# TR-1um cell library — generated by scripts/mklef.py
# source: TR-1um_STDCELL.gds

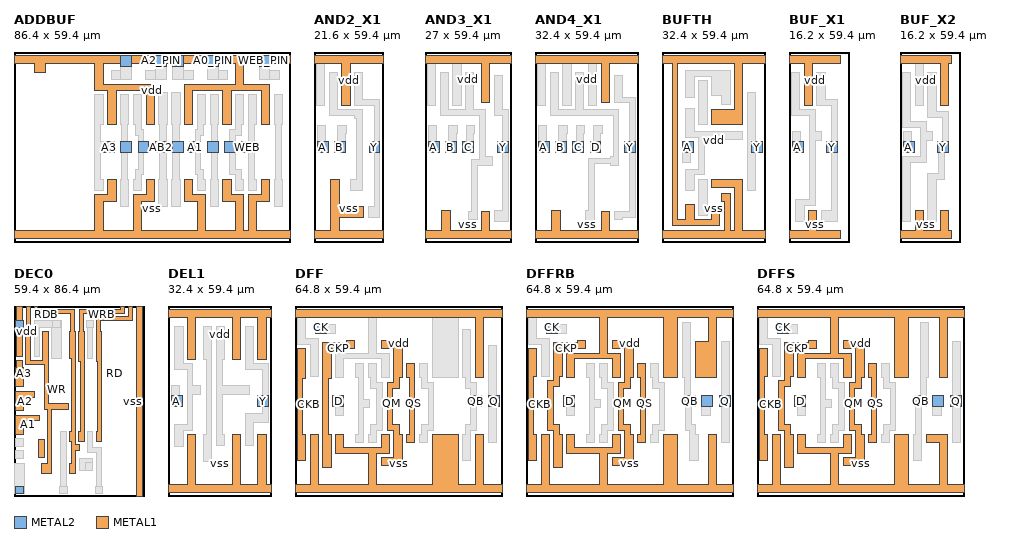
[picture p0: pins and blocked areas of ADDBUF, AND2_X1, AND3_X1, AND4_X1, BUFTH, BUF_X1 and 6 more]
MACRO ADDBUF
  CLASS BLOCK ;
  FOREIGN ADDBUF 48.600 -0.000 ;
  ORIGIN 0.000 0.000 ;
  SIZE 86.400 BY 59.400 ;
  SYMMETRY X Y ;
  PIN A0
    DIRECTION INOUT ;
    USE SIGNAL ;
    PORT
      LAYER METAL2 ;
        RECT 65.800 28.000 69.200 31.400 ;
    END
  END A0
  PIN A0_PIN
    DIRECTION INOUT ;
    USE SIGNAL ;
    PORT
      LAYER METAL2 ;
        RECT 60.400 54.900 63.800 58.300 ;
    END
  END A0_PIN
  PIN A1
    DIRECTION INOUT ;
    USE SIGNAL ;
    PORT
      LAYER METAL2 ;
        RECT 55.000 28.000 58.400 31.400 ;
    END
  END A1
  PIN A1_PIN
    DIRECTION INOUT ;
    USE SIGNAL ;
    PORT
      LAYER METAL2 ;
        RECT 49.600 54.900 53.000 58.300 ;
    END
  END A1_PIN
  PIN A2
    DIRECTION INOUT ;
    USE SIGNAL ;
    PORT
      LAYER METAL2 ;
        RECT 38.800 28.000 42.200 31.400 ;
    END
  END A2
  PIN A2_PIN
    DIRECTION INOUT ;
    USE SIGNAL ;
    PORT
      LAYER METAL2 ;
        RECT 44.200 54.900 47.600 58.300 ;
    END
  END A2_PIN
  PIN A3
    DIRECTION INOUT ;
    USE SIGNAL ;
    PORT
      LAYER METAL2 ;
        RECT 28.000 28.000 31.400 31.400 ;
    END
  END A3
  PIN A3_PIN
    DIRECTION INOUT ;
    USE SIGNAL ;
    PORT
      LAYER METAL2 ;
        RECT 33.400 54.900 36.800 58.300 ;
    END
  END A3_PIN
  PIN AB0
    DIRECTION INOUT ;
    USE SIGNAL ;
    PORT
      LAYER METAL2 ;
        RECT 60.400 28.000 63.800 31.400 ;
    END
  END AB0
  PIN AB1
    DIRECTION INOUT ;
    USE SIGNAL ;
    PORT
      LAYER METAL2 ;
        RECT 49.600 28.000 53.000 31.400 ;
    END
  END AB1
  PIN AB2
    DIRECTION INOUT ;
    USE SIGNAL ;
    PORT
      LAYER METAL2 ;
        RECT 44.200 28.000 47.600 31.400 ;
    END
  END AB2
  PIN AB3
    DIRECTION INOUT ;
    USE SIGNAL ;
    PORT
      LAYER METAL2 ;
        RECT 33.400 28.000 36.800 31.400 ;
    END
  END AB3
  PIN WEB
    DIRECTION INOUT ;
    USE SIGNAL ;
    PORT
      LAYER METAL2 ;
        RECT 71.200 28.000 74.600 31.400 ;
    END
  END WEB
  PIN WEB_PIN
    DIRECTION INOUT ;
    USE SIGNAL ;
    PORT
      LAYER METAL2 ;
        RECT 76.600 54.900 80.000 58.300 ;
    END
  END WEB_PIN
  PIN vdd
    DIRECTION INOUT ;
    USE POWER ;
    SHAPE ABUTMENT ;
    PORT
      LAYER METAL1 ;
        POLYGON 29.300 47.400 29.300 36.600 31.900 36.600 31.900 47.400 41.300 47.400 41.300 36.600 43.900 36.600 43.900 49.200 27.900 49.200 27.900 55.700 69.300 55.700 69.300 49.200 53.300 49.200 53.300 36.600 55.900 36.600 55.900 47.400 65.300 47.400 65.300 36.600 67.900 36.600 67.900 47.400 77.300 47.400 77.300 36.600 79.900 36.600 79.900 49.200 71.900 49.200 71.900 55.700 86.400 55.700 86.400 58.300 0.000 58.300 0.000 55.700 6.400 55.700 6.400 53.100 9.800 53.100 9.800 55.700 25.300 55.700 25.300 47.400 ;
    END
  END vdd
  PIN vss
    DIRECTION INOUT ;
    USE GROUND ;
    SHAPE ABUTMENT ;
    PORT
      LAYER METAL1 ;
        POLYGON 39.900 12.800 43.900 12.800 43.900 19.600 41.300 19.600 41.300 14.800 37.300 14.800 37.300 3.700 27.900 3.700 27.900 12.800 31.900 12.800 31.900 19.600 29.300 19.600 29.300 14.800 25.300 14.800 25.300 3.700 0.000 3.700 0.000 1.100 86.400 1.100 86.400 3.700 75.900 3.700 75.900 12.800 79.900 12.800 79.900 19.600 77.300 19.600 77.300 14.800 73.300 14.800 73.300 3.700 71.900 3.700 71.900 14.800 67.900 14.800 67.900 19.600 65.300 19.600 65.300 12.800 69.300 12.800 69.300 3.700 59.900 3.700 59.900 14.800 55.900 14.800 55.900 19.600 53.300 19.600 53.300 12.800 57.300 12.800 57.300 3.700 39.900 3.700 ;
    END
  END vss
  OBS
    LAYER METAL1 ;
      POLYGON 83.000 53.500 80.000 53.500 80.000 54.300 76.600 54.300 76.600 50.900 83.000 50.900 ;
      POLYGON 36.800 54.300 33.400 54.300 33.400 53.500 30.400 53.500 30.400 50.900 36.800 50.900 ;
      POLYGON 47.600 54.300 44.200 54.300 44.200 53.500 41.200 53.500 41.200 50.900 47.600 50.900 ;
      POLYGON 56.000 53.500 53.000 53.500 53.000 54.300 49.600 54.300 49.600 50.900 56.000 50.900 ;
      POLYGON 66.800 53.500 63.800 53.500 63.800 54.300 60.400 54.300 60.400 50.900 66.800 50.900 ;
      POLYGON 51.600 36.600 51.900 36.600 51.900 46.800 49.300 46.800 49.300 36.600 49.600 36.600 49.600 31.400 51.600 31.400 ;
      POLYGON 47.600 36.600 47.900 36.600 47.900 46.800 45.300 46.800 45.300 36.600 45.600 36.600 45.600 31.400 47.600 31.400 ;
      POLYGON 40.600 35.200 39.900 35.200 39.900 46.000 37.300 46.000 37.300 36.600 38.100 36.600 38.100 33.400 38.800 33.400 38.800 31.400 40.600 31.400 ;
      POLYGON 83.900 19.600 83.600 19.600 83.600 36.600 83.900 36.600 83.900 46.000 81.300 46.000 81.300 36.600 81.600 36.600 81.600 19.600 81.300 19.600 81.300 11.200 83.900 11.200 ;
      POLYGON 27.100 36.600 27.900 36.600 27.900 46.000 25.300 46.000 25.300 16.200 27.900 16.200 27.900 19.600 27.100 19.600 27.100 28.000 28.000 28.000 28.000 31.400 27.100 31.400 ;
      POLYGON 35.600 36.600 35.900 36.600 35.900 46.000 33.300 46.000 33.300 36.600 33.600 36.600 33.600 31.400 35.600 31.400 ;
      POLYGON 58.400 33.400 59.100 33.400 59.100 36.600 59.900 36.600 59.900 46.000 57.300 46.000 57.300 35.200 56.600 35.200 56.600 31.400 58.400 31.400 ;
      POLYGON 63.600 36.600 63.900 36.600 63.900 46.000 61.300 46.000 61.300 36.600 61.600 36.600 61.600 31.400 63.600 31.400 ;
      POLYGON 69.200 33.400 71.100 33.400 71.100 36.600 71.900 36.600 71.900 46.000 69.300 46.000 69.300 35.200 67.400 35.200 67.400 31.400 69.200 31.400 ;
      POLYGON 74.600 28.000 73.300 28.000 73.300 16.200 75.900 16.200 75.900 19.600 75.100 19.600 75.100 36.600 75.900 36.600 75.900 46.000 73.300 46.000 73.300 31.400 74.600 31.400 ;
      POLYGON 45.300 19.600 45.300 11.200 47.900 11.200 47.900 19.600 47.600 19.600 47.600 28.000 45.600 28.000 45.600 19.600 ;
      POLYGON 33.300 19.600 33.300 11.200 35.900 11.200 35.900 19.600 35.600 19.600 35.600 28.000 33.600 28.000 33.600 19.600 ;
      POLYGON 69.300 21.000 69.300 16.200 71.900 16.200 71.900 19.600 71.100 19.600 71.100 22.800 69.200 22.800 69.200 28.000 67.400 28.000 67.400 21.000 ;
      POLYGON 61.300 19.600 61.300 11.200 63.900 11.200 63.900 19.600 63.600 19.600 63.600 28.000 61.600 28.000 61.600 19.600 ;
      POLYGON 38.100 22.800 38.100 19.600 37.300 19.600 37.300 16.200 39.900 16.200 39.900 21.000 40.600 21.000 40.600 28.000 38.800 28.000 38.800 22.800 ;
      POLYGON 57.300 21.000 57.300 16.200 59.900 16.200 59.900 19.600 59.100 19.600 59.100 22.800 58.400 22.800 58.400 28.000 56.600 28.000 56.600 21.000 ;
      POLYGON 49.300 19.600 49.300 11.200 51.900 11.200 51.900 19.600 51.600 19.600 51.600 28.000 49.600 28.000 49.600 19.600 ;
    LAYER METAL2 ;
      RECT 33.400 50.900 36.800 54.900 ;
      RECT 49.600 50.900 53.000 54.900 ;
      RECT 60.400 50.900 63.800 54.900 ;
      RECT 76.600 50.900 80.000 54.900 ;
      RECT 44.200 50.900 47.600 54.900 ;
  END
END ADDBUF

MACRO AND2_X1
  CLASS CORE ;
  FOREIGN AND2_X1 -0.000 -0.000 ;
  ORIGIN 0.000 0.000 ;
  SIZE 21.600 BY 59.400 ;
  SITE TR1UM ;
  SYMMETRY X Y ;
  PIN A
    DIRECTION INOUT ;
    USE SIGNAL ;
    PORT
      LAYER METAL2 ;
        RECT 1.000 28.000 4.400 31.400 ;
    END
  END A
  PIN B
    DIRECTION INOUT ;
    USE SIGNAL ;
    PORT
      LAYER METAL2 ;
        RECT 6.400 28.000 9.800 31.400 ;
    END
  END B
  PIN Y
    DIRECTION INOUT ;
    USE SIGNAL ;
    PORT
      LAYER METAL2 ;
        RECT 17.200 28.000 20.600 31.400 ;
    END
  END Y
  PIN vdd
    DIRECTION INOUT ;
    USE POWER ;
    SHAPE ABUTMENT ;
    PORT
      LAYER METAL1 ;
        POLYGON 11.300 42.700 11.300 55.700 21.600 55.700 21.600 58.300 0.000 58.300 0.000 55.700 8.700 55.700 8.700 42.700 ;
    END
  END vdd
  PIN vss
    DIRECTION INOUT ;
    USE GROUND ;
    SHAPE ABUTMENT ;
    PORT
      LAYER METAL1 ;
        POLYGON 0.000 1.100 21.600 1.100 21.600 3.700 7.900 3.700 7.900 7.700 15.500 7.700 15.500 11.100 7.900 11.100 7.900 19.600 5.300 19.600 5.300 3.700 0.000 3.700 ;
    END
  END vss
  OBS
    LAYER METAL1 ;
      RECT 0.700 42.700 3.300 55.700 ;
      POLYGON 20.600 44.600 15.300 44.600 15.300 52.900 12.700 52.900 12.700 42.700 18.800 42.700 18.800 31.400 20.600 31.400 ;
      POLYGON 15.200 41.300 7.300 41.300 7.300 52.900 4.700 52.900 4.700 39.500 12.600 39.500 12.600 38.700 13.400 38.700 13.400 19.600 11.500 19.600 11.500 16.200 15.200 16.200 ;
      POLYGON 9.800 33.900 10.100 33.900 10.100 36.500 7.500 36.500 7.500 31.400 9.800 31.400 ;
      RECT 1.000 31.400 3.600 36.500 ;
      POLYGON 16.900 11.100 16.900 7.700 20.600 7.700 20.600 28.000 18.800 28.000 18.800 11.100 ;
  END
END AND2_X1

MACRO AND3_X1
  CLASS CORE ;
  FOREIGN AND3_X1 -0.000 -0.000 ;
  ORIGIN 0.000 0.000 ;
  SIZE 27.000 BY 59.400 ;
  SITE TR1UM ;
  SYMMETRY X Y ;
  PIN A
    DIRECTION INOUT ;
    USE SIGNAL ;
    PORT
      LAYER METAL2 ;
        RECT 1.000 28.000 4.400 31.400 ;
    END
  END A
  PIN B
    DIRECTION INOUT ;
    USE SIGNAL ;
    PORT
      LAYER METAL2 ;
        RECT 6.400 28.000 9.800 31.400 ;
    END
  END B
  PIN C
    DIRECTION INOUT ;
    USE SIGNAL ;
    PORT
      LAYER METAL2 ;
        RECT 11.800 28.000 15.200 31.400 ;
    END
  END C
  PIN Y
    DIRECTION INOUT ;
    USE SIGNAL ;
    PORT
      LAYER METAL2 ;
        RECT 22.600 28.000 26.000 31.400 ;
    END
  END Y
  PIN vdd
    DIRECTION INOUT ;
    USE POWER ;
    SHAPE ABUTMENT ;
    PORT
      LAYER METAL1 ;
        POLYGON 20.300 43.500 20.300 55.700 27.000 55.700 27.000 58.300 0.000 58.300 0.000 55.700 17.700 55.700 17.700 43.500 ;
    END
  END vdd
  PIN vss
    DIRECTION INOUT ;
    USE GROUND ;
    SHAPE ABUTMENT ;
    PORT
      LAYER METAL1 ;
        POLYGON 0.000 1.100 27.000 1.100 27.000 3.700 20.300 3.700 20.300 9.500 17.700 9.500 17.700 3.700 7.900 3.700 7.900 9.900 5.300 9.900 5.300 3.700 0.000 3.700 ;
    END
  END vss
  OBS
    LAYER METAL1 ;
      RECT 8.700 42.700 11.300 55.700 ;
      RECT 0.700 42.700 3.300 55.700 ;
      POLYGON 16.300 24.000 21.200 24.000 21.200 26.600 18.900 26.600 18.900 41.300 15.300 41.300 15.300 52.900 12.700 52.900 12.700 41.300 7.300 41.300 7.300 52.900 4.700 52.900 4.700 39.500 17.100 39.500 17.100 25.800 14.500 25.800 14.500 9.500 13.700 9.500 13.700 6.900 16.300 6.900 ;
      POLYGON 26.000 41.300 24.300 41.300 24.300 52.100 21.700 52.100 21.700 39.500 24.200 39.500 24.200 31.400 26.000 31.400 ;
      RECT 1.000 31.400 3.600 36.500 ;
      POLYGON 9.800 33.900 10.100 33.900 10.100 36.500 7.500 36.500 7.500 31.400 9.800 31.400 ;
      POLYGON 15.200 33.900 15.500 33.900 15.500 36.500 12.900 36.500 12.900 31.400 15.200 31.400 ;
      POLYGON 21.700 9.900 21.700 6.500 26.000 6.500 26.000 28.000 24.200 28.000 24.200 9.900 ;
  END
END AND3_X1

MACRO AND4_X1
  CLASS CORE ;
  FOREIGN AND4_X1 -0.000 -0.000 ;
  ORIGIN 0.000 0.000 ;
  SIZE 32.400 BY 59.400 ;
  SITE TR1UM ;
  SYMMETRY X Y ;
  PIN A
    DIRECTION INOUT ;
    USE SIGNAL ;
    PORT
      LAYER METAL2 ;
        RECT 1.000 28.000 4.400 31.400 ;
    END
  END A
  PIN B
    DIRECTION INOUT ;
    USE SIGNAL ;
    PORT
      LAYER METAL2 ;
        RECT 6.400 28.000 9.800 31.400 ;
    END
  END B
  PIN C
    DIRECTION INOUT ;
    USE SIGNAL ;
    PORT
      LAYER METAL2 ;
        RECT 11.800 28.000 15.200 31.400 ;
    END
  END C
  PIN D
    DIRECTION INOUT ;
    USE SIGNAL ;
    PORT
      LAYER METAL2 ;
        RECT 17.200 28.000 20.600 31.400 ;
    END
  END D
  PIN Y
    DIRECTION INOUT ;
    USE SIGNAL ;
    PORT
      LAYER METAL2 ;
        RECT 28.000 28.000 31.400 31.400 ;
    END
  END Y
  PIN vdd
    DIRECTION INOUT ;
    USE POWER ;
    SHAPE ABUTMENT ;
    PORT
      LAYER METAL1 ;
        POLYGON 23.400 43.500 23.400 55.700 32.400 55.700 32.400 58.300 0.000 58.300 0.000 55.700 20.800 55.700 20.800 43.500 ;
    END
  END vdd
  PIN vss
    DIRECTION INOUT ;
    USE GROUND ;
    SHAPE ABUTMENT ;
    PORT
      LAYER METAL1 ;
        POLYGON 0.000 1.100 32.400 1.100 32.400 3.700 23.400 3.700 23.400 9.500 20.800 9.500 20.800 3.700 7.900 3.700 7.900 9.900 5.300 9.900 5.300 3.700 0.000 3.700 ;
    END
  END vss
  OBS
    LAYER METAL1 ;
      RECT 16.700 42.700 19.300 55.700 ;
      RECT 0.700 42.700 3.300 55.700 ;
      RECT 8.700 42.700 11.300 55.700 ;
      POLYGON 15.900 6.500 18.500 6.500 18.500 24.400 23.600 24.400 23.600 24.000 26.200 24.000 26.200 41.300 15.300 41.300 15.300 52.900 12.700 52.900 12.700 41.300 7.300 41.300 7.300 52.900 4.700 52.900 4.700 39.500 24.400 39.500 24.400 26.600 23.600 26.600 23.600 26.200 16.700 26.200 16.700 9.900 15.900 9.900 ;
      POLYGON 31.400 45.300 27.400 45.300 27.400 52.100 24.800 52.100 24.800 43.500 29.600 43.500 29.600 31.400 31.400 31.400 ;
      POLYGON 20.600 33.900 21.000 33.900 21.000 36.500 18.300 36.500 18.300 31.400 20.600 31.400 ;
      POLYGON 15.200 33.900 15.500 33.900 15.500 36.500 12.900 36.500 12.900 31.400 15.200 31.400 ;
      RECT 1.000 31.400 3.600 36.500 ;
      POLYGON 9.800 33.900 10.100 33.900 10.100 36.500 7.500 36.500 7.500 31.400 9.800 31.400 ;
      POLYGON 24.800 6.900 27.400 6.900 27.400 7.700 31.400 7.700 31.400 28.000 29.600 28.000 29.600 9.500 24.800 9.500 ;
  END
END AND4_X1

MACRO BUFTH
  CLASS CORE ;
  FOREIGN BUFTH -0.000 -0.000 ;
  ORIGIN 0.000 0.000 ;
  SIZE 32.400 BY 59.400 ;
  SITE TR1UM ;
  SYMMETRY X Y ;
  PIN A
    DIRECTION INOUT ;
    USE SIGNAL ;
    PORT
      LAYER METAL2 ;
        RECT 6.400 28.000 9.800 31.400 ;
    END
  END A
  PIN Y
    DIRECTION INOUT ;
    USE SIGNAL ;
    PORT
      LAYER METAL2 ;
        RECT 28.000 28.000 31.400 31.400 ;
    END
  END Y
  PIN vdd
    DIRECTION INOUT ;
    USE POWER ;
    SHAPE ABUTMENT ;
    PORT
      LAYER METAL1 ;
        POLYGON 18.100 5.100 18.100 10.900 15.500 10.900 15.500 6.900 10.100 6.900 10.100 11.700 7.500 11.700 7.500 6.900 5.000 6.900 5.000 55.700 22.700 55.700 22.700 41.300 15.500 41.300 15.500 36.600 25.300 36.600 25.300 55.700 32.400 55.700 32.400 58.300 0.000 58.300 0.000 55.700 3.200 55.700 3.200 5.100 ;
    END
  END vdd
  PIN vss
    DIRECTION INOUT ;
    USE GROUND ;
    SHAPE ABUTMENT ;
    PORT
      LAYER METAL1 ;
        POLYGON 0.000 1.100 32.400 1.100 32.400 3.700 25.300 3.700 25.300 19.600 15.500 19.600 15.500 17.000 22.700 17.000 22.700 3.700 21.300 3.700 21.300 15.300 18.700 15.300 18.700 12.700 19.500 12.700 19.500 3.700 0.000 3.700 ;
    END
  END vss
  OBS
    LAYER METAL1 ;
      POLYGON 21.300 53.600 7.500 53.600 7.500 45.300 10.100 45.300 10.100 51.800 15.500 51.800 15.500 45.700 18.700 45.700 18.700 43.100 21.300 43.100 ;
      RECT 11.500 36.600 14.100 50.400 ;
      POLYGON 29.300 46.800 26.700 46.800 26.700 16.200 29.300 16.200 29.300 28.000 28.000 28.000 28.000 31.400 29.300 31.400 ;
      POLYGON 10.100 21.000 13.200 21.000 13.200 32.000 25.300 32.000 25.300 34.600 10.100 34.600 10.100 41.700 7.500 41.700 7.500 32.800 11.400 32.800 11.400 22.800 7.500 22.800 7.500 16.200 10.100 16.200 ;
      RECT 6.400 25.000 9.000 28.000 ;
      RECT 11.500 8.300 14.100 19.600 ;
  END
END BUFTH

MACRO BUF_X1
  CLASS CORE ;
  FOREIGN BUF_X1 -0.000 -0.000 ;
  ORIGIN 0.000 0.000 ;
  SIZE 16.200 BY 59.400 ;
  SITE TR1UM ;
  SYMMETRY X Y ;
  PIN A
    DIRECTION INOUT ;
    USE SIGNAL ;
    PORT
      LAYER METAL2 ;
        RECT 1.000 28.000 4.400 31.400 ;
    END
  END A
  PIN Y
    DIRECTION INOUT ;
    USE SIGNAL ;
    PORT
      LAYER METAL2 ;
        RECT 11.800 28.000 15.200 31.400 ;
    END
  END Y
  PIN vdd
    DIRECTION INOUT ;
    USE POWER ;
    SHAPE ABUTMENT ;
    PORT
      LAYER METAL1 ;
        POLYGON 7.300 42.700 7.300 55.700 16.200 55.700 16.200 58.300 0.000 58.300 0.000 55.700 4.700 55.700 4.700 42.700 ;
    END
  END vdd
  PIN vss
    DIRECTION INOUT ;
    USE GROUND ;
    SHAPE ABUTMENT ;
    PORT
      LAYER METAL1 ;
        POLYGON 0.000 1.100 16.200 1.100 16.200 3.700 8.700 3.700 8.700 9.900 6.100 9.900 6.100 3.700 0.000 3.700 ;
    END
  END vss
  OBS
    LAYER METAL1 ;
      POLYGON 15.200 44.500 11.300 44.500 11.300 52.900 8.700 52.900 8.700 42.700 13.400 42.700 13.400 31.400 15.200 31.400 ;
      POLYGON 4.700 11.500 8.300 11.500 8.300 31.800 10.100 31.800 10.100 34.400 8.300 34.400 8.300 41.300 3.300 41.300 3.300 52.900 0.700 52.900 0.700 39.500 6.500 39.500 6.500 13.300 2.100 13.300 2.100 6.500 4.700 6.500 ;
      RECT 1.000 31.400 3.600 34.400 ;
      POLYGON 10.100 9.900 10.100 6.500 15.200 6.500 15.200 28.000 13.400 28.000 13.400 9.900 ;
  END
END BUF_X1

MACRO BUF_X2
  CLASS CORE ;
  FOREIGN BUF_X2 -0.000 -0.000 ;
  ORIGIN 0.000 0.000 ;
  SIZE 16.200 BY 59.400 ;
  SITE TR1UM ;
  SYMMETRY X Y ;
  PIN A
    DIRECTION INOUT ;
    USE SIGNAL ;
    PORT
      LAYER METAL2 ;
        RECT 1.000 28.000 4.400 31.400 ;
    END
  END A
  PIN Y
    DIRECTION INOUT ;
    USE SIGNAL ;
    PORT
      LAYER METAL2 ;
        RECT 11.800 28.000 15.200 31.400 ;
    END
  END Y
  PIN vdd
    DIRECTION INOUT ;
    USE POWER ;
    SHAPE ABUTMENT ;
    PORT
      LAYER METAL1 ;
        POLYGON 15.300 42.700 15.300 55.700 16.200 55.700 16.200 58.300 0.000 58.300 0.000 55.700 12.700 55.700 12.700 42.700 ;
    END
  END vdd
  PIN vss
    DIRECTION INOUT ;
    USE GROUND ;
    SHAPE ABUTMENT ;
    PORT
      LAYER METAL1 ;
        POLYGON 0.000 1.100 16.200 1.100 16.200 3.700 15.300 3.700 15.300 9.900 12.700 9.900 12.700 3.700 7.300 3.700 7.300 9.900 4.700 9.900 4.700 3.700 0.000 3.700 ;
    END
  END vss
  OBS
    LAYER METAL1 ;
      RECT 4.700 42.700 7.300 55.700 ;
      POLYGON 15.200 40.800 11.300 40.800 11.300 52.900 8.700 52.900 8.700 39.000 13.400 39.000 13.400 31.400 15.200 31.400 ;
      POLYGON 3.300 24.800 8.300 24.800 8.300 31.800 10.100 31.800 10.100 34.400 8.300 34.400 8.300 37.600 3.300 37.600 3.300 52.900 0.700 52.900 0.700 35.800 6.500 35.800 6.500 26.600 0.700 26.600 0.700 6.500 3.300 6.500 ;
      RECT 1.000 31.400 3.600 34.400 ;
      POLYGON 8.700 21.400 8.700 6.500 11.300 6.500 11.300 19.600 13.800 19.600 13.800 28.000 12.000 28.000 12.000 21.400 ;
  END
END BUF_X2

MACRO DEC0
  CLASS BLOCK ;
  FOREIGN DEC0 2.400 -0.000 ;
  ORIGIN 0.000 0.000 ;
  SIZE 59.400 BY 86.400 ;
  SYMMETRY X Y ;
  PIN A1
    DIRECTION INOUT ;
    USE SIGNAL ;
    PORT
      LAYER METAL1 ;
        POLYGON 4.100 34.200 11.600 34.200 11.600 36.800 0.700 36.800 0.700 28.000 4.100 28.000 ;
        RECT 11.200 17.600 13.800 25.600 ;
    END
  END A1
  PIN A2
    DIRECTION INOUT ;
    USE SIGNAL ;
    PORT
      LAYER METAL1 ;
        POLYGON 4.100 45.000 9.400 45.000 9.400 47.600 0.700 47.600 0.700 38.800 4.100 38.800 ;
    END
  END A2
  PIN A3
    DIRECTION INOUT ;
    USE SIGNAL ;
    PORT
      LAYER METAL1 ;
        POLYGON 4.100 58.400 3.700 58.400 3.700 61.400 1.100 61.400 1.100 58.400 0.700 58.400 0.700 49.600 4.100 49.600 ;
    END
  END A3
  PIN RD
    DIRECTION INOUT ;
    USE SIGNAL ;
    PORT
      LAYER METAL1 ;
        POLYGON 37.300 61.000 38.100 61.000 38.100 29.200 37.300 29.200 37.300 24.600 39.900 24.600 39.900 74.900 39.500 74.900 39.500 79.700 53.900 79.700 53.900 86.400 52.100 86.400 52.100 81.500 37.700 81.500 37.700 74.900 37.300 74.900 ;
    END
  END RD
  PIN RDB
    DIRECTION INOUT ;
    USE SIGNAL ;
    PORT
      LAYER METAL1 ;
        POLYGON 5.100 59.800 13.900 59.800 13.900 39.400 15.200 39.400 15.200 14.700 12.700 14.700 12.700 10.100 17.000 10.100 17.000 39.400 24.700 39.400 24.700 42.000 15.700 42.000 15.700 74.900 13.100 74.900 13.100 61.600 7.700 61.600 7.700 74.900 7.300 74.900 7.300 86.400 5.500 86.400 5.500 74.900 5.100 74.900 ;
    END
  END RDB
  PIN WR
    DIRECTION INOUT ;
    USE SIGNAL ;
    PORT
      LAYER METAL1 ;
        POLYGON 25.300 62.700 26.100 62.700 26.100 29.200 25.300 29.200 25.300 24.600 26.100 24.600 26.100 14.700 25.300 14.700 25.300 10.100 27.900 10.100 27.900 20.600 29.700 20.600 29.700 23.200 27.900 23.200 27.900 74.900 27.500 74.900 27.500 84.700 10.900 84.700 10.900 86.400 9.100 86.400 9.100 82.900 25.700 82.900 25.700 74.900 25.300 74.900 ;
    END
  END WR
  PIN WRB
    DIRECTION INOUT ;
    USE SIGNAL ;
    PORT
      LAYER METAL1 ;
        POLYGON 29.300 61.000 30.100 61.000 30.100 29.200 29.300 29.200 29.300 24.600 31.900 24.600 31.900 74.900 31.500 74.900 31.500 82.900 50.300 82.900 50.300 86.400 48.500 86.400 48.500 84.700 29.700 84.700 29.700 74.900 29.300 74.900 ;
    END
  END WRB
  PIN vdd
    DIRECTION INOUT ;
    USE POWER ;
    SHAPE ABUTMENT ;
    PORT
      LAYER METAL2 ;
        RECT 0.700 76.600 4.100 80.000 ;
      LAYER METAL1 ;
        POLYGON 3.700 76.600 4.100 76.600 4.100 80.000 3.700 80.000 3.700 86.400 1.100 86.400 1.100 80.000 0.700 80.000 0.700 76.600 1.100 76.600 1.100 63.500 3.700 63.500 ;
    END
  END vdd
  PIN vss
    DIRECTION INOUT ;
    USE GROUND ;
    SHAPE ABUTMENT ;
    PORT
      LAYER METAL2 ;
        RECT 0.700 1.000 4.100 4.400 ;
      LAYER METAL1 ;
        RECT 55.700 0.000 58.300 86.400 ;
    END
  END vss
  OBS
    LAYER METAL1 ;
      POLYGON 9.100 63.500 11.700 63.500 11.700 76.600 17.100 76.600 17.100 62.700 21.700 62.700 21.700 80.000 9.100 80.000 ;
      POLYGON 32.900 76.600 33.300 76.600 33.300 62.700 35.900 62.700 35.900 76.600 36.300 76.600 36.300 80.000 32.900 80.000 ;
      POLYGON 40.300 4.400 39.900 4.400 39.900 22.200 35.900 22.200 35.900 29.200 33.300 29.200 33.300 19.800 37.300 19.800 37.300 4.400 36.900 4.400 36.900 1.000 40.300 1.000 ;
      POLYGON 24.300 4.400 23.900 4.400 23.900 29.200 21.300 29.200 21.300 4.400 20.900 4.400 20.900 1.000 24.300 1.000 ;
      RECT 0.700 22.600 4.100 26.000 ;
      RECT 0.700 17.200 4.100 20.600 ;
      RECT 29.600 11.800 35.900 17.200 ;
      POLYGON 4.100 4.400 4.100 1.000 4.700 1.000 4.700 14.700 0.100 14.700 0.100 1.000 0.700 1.000 0.700 4.400 ;
    LAYER METAL2 ;
      RECT 17.700 76.600 21.100 80.000 ;
      RECT 32.900 76.600 36.300 80.000 ;
      RECT 32.500 11.800 35.900 15.200 ;
      RECT 36.900 1.000 40.300 4.400 ;
      RECT 20.900 1.000 24.300 4.400 ;
  END
END DEC0

MACRO DEC16
  CLASS BLOCK ;
  FOREIGN DEC16 57.000 0.000 ;
  ORIGIN 0.000 0.000 ;
  SIZE 878.400 BY 86.400 ;
  SYMMETRY X Y ;
  # ★ ピン未定義: GDS のトップにラベル/(49,1) 形状を入れて再生成すること
  OBS
    LAYER METAL1 ;
      RECT 0.000 0.000 878.400 86.400 ;
    LAYER METAL2 ;
      RECT 0.000 0.000 878.400 86.400 ;
  END
END DEC16

MACRO DEC2
  CLASS BLOCK ;
  FOREIGN DEC2 57.000 0.000 ;
  ORIGIN 0.000 0.000 ;
  SIZE 114.000 BY 86.400 ;
  SYMMETRY X Y ;
  # ★ ピン未定義: GDS のトップにラベル/(49,1) 形状を入れて再生成すること
  OBS
    LAYER METAL1 ;
      RECT 0.000 0.000 114.000 86.400 ;
    LAYER METAL2 ;
      RECT 0.000 0.000 114.000 86.400 ;
  END
END DEC2

MACRO DEL1
  CLASS CORE ;
  FOREIGN DEL1 -0.000 -0.000 ;
  ORIGIN 0.000 0.000 ;
  SIZE 32.400 BY 59.400 ;
  SITE TR1UM ;
  SYMMETRY X Y ;
  PIN A
    DIRECTION INOUT ;
    USE SIGNAL ;
    PORT
      LAYER METAL2 ;
        RECT 1.000 28.000 4.400 31.400 ;
    END
  END A
  PIN Y
    DIRECTION INOUT ;
    USE SIGNAL ;
    PORT
      LAYER METAL2 ;
        RECT 28.000 28.000 31.400 31.400 ;
    END
  END Y
  PIN vdd
    DIRECTION INOUT ;
    USE POWER ;
    SHAPE ABUTMENT ;
    PORT
      LAYER METAL1 ;
        POLYGON 8.700 55.700 20.100 55.700 20.100 42.700 22.700 42.700 22.700 55.700 28.100 55.700 28.100 42.700 30.700 42.700 30.700 55.700 32.400 55.700 32.400 58.300 0.000 58.300 0.000 55.700 6.100 55.700 6.100 42.700 8.700 42.700 ;
    END
  END vdd
  PIN vss
    DIRECTION INOUT ;
    USE GROUND ;
    SHAPE ABUTMENT ;
    PORT
      LAYER METAL1 ;
        POLYGON 32.400 3.700 30.700 3.700 30.700 19.100 28.100 19.100 28.100 3.700 22.700 3.700 22.700 19.100 20.100 19.100 20.100 3.700 8.700 3.700 8.700 19.100 6.100 19.100 6.100 3.700 0.000 3.700 0.000 1.100 32.400 1.100 ;
    END
  END vss
  OBS
    LAYER METAL1 ;
      POLYGON 31.400 41.300 26.700 41.300 26.700 52.900 24.100 52.900 24.100 39.500 29.600 39.500 29.600 31.400 31.400 31.400 ;
      POLYGON 13.700 52.900 11.100 52.900 11.100 42.700 11.900 42.700 11.900 19.100 11.100 19.100 11.100 10.700 13.700 10.700 ;
      POLYGON 17.700 19.100 16.900 19.100 16.900 31.800 25.500 31.800 25.500 34.400 16.900 34.400 16.900 42.700 17.700 42.700 17.700 52.900 15.100 52.900 15.100 15.700 17.700 15.700 ;
      POLYGON 4.700 20.500 7.800 20.500 7.800 31.800 10.100 31.800 10.100 34.400 7.800 34.400 7.800 41.300 4.700 41.300 4.700 52.900 2.100 52.900 2.100 39.500 6.000 39.500 6.000 22.300 2.100 22.300 2.100 15.500 4.700 15.500 ;
      RECT 1.000 31.400 3.600 34.400 ;
      POLYGON 24.100 25.800 24.100 15.700 26.700 15.700 26.700 22.900 31.400 22.900 31.400 28.000 29.600 28.000 29.600 25.800 ;
  END
END DEL1

MACRO DFF
  CLASS CORE ;
  FOREIGN DFF -0.000 -0.000 ;
  ORIGIN 0.000 0.000 ;
  SIZE 64.800 BY 59.400 ;
  SITE TR1UM ;
  SYMMETRY X Y ;
  PIN CK
    DIRECTION INOUT ;
    USE SIGNAL ;
    PORT
      LAYER METAL2 ;
        RECT 6.400 50.900 9.800 54.300 ;
    END
  END CK
  PIN CKB
    DIRECTION INOUT ;
    USE SIGNAL ;
    PORT
      LAYER METAL1 ;
        POLYGON 3.300 19.200 2.500 19.200 2.500 36.600 3.300 36.600 3.300 46.100 0.700 46.100 0.700 11.200 3.300 11.200 ;
    END
  END CKB
  PIN CKP
    DIRECTION INOUT ;
    USE SIGNAL ;
    PORT
      LAYER METAL1 ;
        POLYGON 11.300 19.200 10.500 19.200 10.500 22.400 10.400 22.400 10.400 34.300 10.500 34.300 10.500 36.600 11.300 36.600 11.300 46.100 18.700 46.100 18.700 48.700 16.100 48.700 16.100 47.900 8.700 47.900 8.700 36.100 8.600 36.100 8.600 20.600 8.700 20.600 8.700 9.000 11.300 9.000 ;
    END
  END CKP
  PIN D
    DIRECTION INOUT ;
    USE SIGNAL ;
    PORT
      LAYER METAL2 ;
        RECT 11.800 27.900 15.200 31.300 ;
    END
  END D
  PIN Q
    DIRECTION INOUT ;
    USE SIGNAL ;
    PORT
      LAYER METAL2 ;
        RECT 60.400 27.900 63.800 31.300 ;
    END
  END Q
  PIN QB
    DIRECTION INOUT ;
    USE SIGNAL ;
    PORT
      LAYER METAL2 ;
        RECT 55.000 27.900 58.400 31.300 ;
    END
  END QB
  PIN QM
    DIRECTION INOUT ;
    USE SIGNAL ;
    PORT
      LAYER METAL1 ;
        POLYGON 29.500 10.200 33.500 10.200 33.500 19.200 32.700 19.200 32.700 22.400 30.600 22.400 30.600 33.700 32.700 33.700 32.700 36.900 33.500 36.900 33.500 47.900 29.500 47.900 29.500 48.700 26.900 48.700 26.900 46.100 30.900 46.100 30.900 35.500 28.800 35.500 28.800 20.600 30.900 20.600 30.900 12.000 26.900 12.000 26.900 9.400 29.500 9.400 ;
    END
  END QM
  PIN QS
    DIRECTION INOUT ;
    USE SIGNAL ;
    PORT
      LAYER METAL1 ;
        POLYGON 37.500 27.700 39.300 27.700 39.300 30.300 37.500 30.300 37.500 41.500 34.900 41.500 34.900 36.900 35.700 36.900 35.700 19.200 34.900 19.200 34.900 16.600 37.500 16.600 ;
    END
  END QS
  PIN vdd
    DIRECTION INOUT ;
    USE POWER ;
    SHAPE ABUTMENT ;
    PORT
      LAYER METAL1 ;
        POLYGON 59.000 36.900 59.000 55.700 64.800 55.700 64.800 58.300 0.000 58.300 0.000 55.700 56.400 55.700 56.400 36.900 ;
    END
  END vdd
  PIN vss
    DIRECTION INOUT ;
    USE GROUND ;
    SHAPE ABUTMENT ;
    PORT
      LAYER METAL1 ;
        POLYGON 0.000 1.100 64.800 1.100 64.800 3.700 59.000 3.700 59.000 19.200 56.400 19.200 56.400 3.700 51.000 3.700 51.000 19.200 42.900 19.200 42.900 3.700 25.500 3.700 25.500 13.400 29.500 13.400 29.500 19.200 26.900 19.200 26.900 15.200 15.300 15.200 15.300 19.200 12.700 19.200 12.700 13.400 22.900 13.400 22.900 3.700 7.300 3.700 7.300 19.200 4.700 19.200 4.700 3.700 0.000 3.700 ;
    END
  END vss
  OBS
    LAYER METAL1 ;
      RECT 42.900 36.900 51.000 55.700 ;
      POLYGON 7.300 49.300 3.300 49.300 3.300 55.700 0.700 55.700 0.700 47.500 4.700 47.500 4.700 37.400 7.300 37.400 ;
      POLYGON 15.300 42.900 26.900 42.900 26.900 36.900 29.500 36.900 29.500 44.700 25.500 44.700 25.500 55.700 22.900 55.700 22.900 44.700 12.700 44.700 12.700 36.900 15.300 36.900 ;
      RECT 9.800 50.900 12.800 53.500 ;
      POLYGON 56.800 35.500 55.000 35.500 55.000 52.000 52.400 52.000 52.400 36.900 53.200 36.900 53.200 33.700 55.000 33.700 55.000 31.300 56.800 31.300 ;
      RECT 60.400 31.300 63.000 47.000 ;
      POLYGON 21.500 27.700 23.200 27.700 23.200 30.300 21.500 30.300 21.500 41.500 18.900 41.500 18.900 36.900 19.700 36.900 19.700 19.200 18.900 19.200 18.900 16.600 21.500 16.600 ;
      POLYGON 25.500 20.600 27.400 20.600 27.400 35.500 25.500 35.500 25.500 41.500 22.900 41.500 22.900 36.900 23.700 36.900 23.700 33.700 25.600 33.700 25.600 22.400 23.700 22.400 23.700 19.200 22.900 19.200 22.900 16.600 25.500 16.600 ;
      POLYGON 41.500 20.600 43.400 20.600 43.400 35.500 41.500 35.500 41.500 41.500 38.900 41.500 38.900 36.900 39.700 36.900 39.700 33.700 41.600 33.700 41.600 22.400 39.700 22.400 39.700 19.200 38.900 19.200 38.900 16.600 41.500 16.600 ;
      RECT 12.600 25.100 15.200 27.900 ;
      POLYGON 53.200 22.400 53.200 19.200 52.400 19.200 52.400 11.200 55.000 11.200 55.000 20.600 56.800 20.600 56.800 27.900 55.000 27.900 55.000 22.400 ;
      RECT 60.400 16.600 63.000 27.900 ;
  END
END DFF

MACRO DFFRB
  CLASS CORE ;
  FOREIGN DFFRB -0.000 -0.000 ;
  ORIGIN 0.000 0.000 ;
  SIZE 64.800 BY 59.400 ;
  SITE TR1UM ;
  SYMMETRY X Y ;
  PIN CK
    DIRECTION INOUT ;
    USE SIGNAL ;
    PORT
      LAYER METAL2 ;
        RECT 6.400 50.900 9.800 54.300 ;
    END
  END CK
  PIN CKB
    DIRECTION INOUT ;
    USE SIGNAL ;
    PORT
      LAYER METAL1 ;
        POLYGON 3.300 19.200 2.500 19.200 2.500 37.500 3.300 37.500 3.300 46.100 0.700 46.100 0.700 11.200 3.300 11.200 ;
    END
  END CKB
  PIN CKP
    DIRECTION INOUT ;
    USE SIGNAL ;
    PORT
      LAYER METAL1 ;
        POLYGON 10.500 19.200 10.500 22.400 8.600 22.400 8.600 34.300 10.500 34.300 10.500 37.500 11.300 37.500 11.300 46.100 18.700 46.100 18.700 48.700 16.100 48.700 16.100 47.900 8.700 47.900 8.700 36.100 6.800 36.100 6.800 20.600 8.700 20.600 8.700 9.000 11.300 9.000 11.300 19.200 ;
    END
  END CKP
  PIN D
    DIRECTION INOUT ;
    USE SIGNAL ;
    PORT
      LAYER METAL2 ;
        RECT 11.800 27.900 15.200 31.300 ;
    END
  END D
  PIN Q
    DIRECTION INOUT ;
    USE SIGNAL ;
    PORT
      LAYER METAL2 ;
        RECT 60.400 27.900 63.800 31.300 ;
    END
  END Q
  PIN QB
    DIRECTION INOUT ;
    USE SIGNAL ;
    PORT
      LAYER METAL2 ;
        RECT 49.600 27.900 53.000 31.300 ;
        RECT 49.600 27.900 53.000 31.300 ;
    END
  END QB
  PIN QM
    DIRECTION INOUT ;
    USE SIGNAL ;
    PORT
      LAYER METAL1 ;
        POLYGON 26.900 9.400 29.500 9.400 29.500 10.200 33.500 10.200 33.500 19.200 32.700 19.200 32.700 22.400 30.600 22.400 30.600 33.700 32.700 33.700 32.700 36.900 33.500 36.900 33.500 47.900 29.500 47.900 29.500 48.700 26.900 48.700 26.900 46.100 30.900 46.100 30.900 35.500 28.800 35.500 28.800 20.600 30.900 20.600 30.900 12.000 26.900 12.000 ;
    END
  END QM
  PIN QS
    DIRECTION INOUT ;
    USE SIGNAL ;
    PORT
      LAYER METAL1 ;
        POLYGON 37.500 27.700 39.300 27.700 39.300 30.300 37.500 30.300 37.500 41.500 34.900 41.500 34.900 36.900 35.700 36.900 35.700 19.200 34.900 19.200 34.900 16.600 37.500 16.600 ;
    END
  END QS
  PIN RSTB
    DIRECTION INOUT ;
    USE SIGNAL ;
    PORT
      LAYER METAL2 ;
        RECT 55.000 27.900 58.400 31.300 ;
    END
  END RSTB
  PIN vdd
    DIRECTION INOUT ;
    USE POWER ;
    SHAPE ABUTMENT ;
    PORT
      LAYER METAL1 ;
        POLYGON 57.000 48.400 52.900 48.400 52.900 36.900 59.600 36.900 59.600 55.700 64.800 55.700 64.800 58.300 0.000 58.300 0.000 55.700 22.900 55.700 22.900 44.700 12.700 44.700 12.700 36.900 15.300 36.900 15.300 42.900 26.900 42.900 26.900 36.900 29.500 36.900 29.500 44.700 25.500 44.700 25.500 55.700 42.900 55.700 42.900 36.900 47.500 36.900 47.500 55.700 57.000 55.700 ;
    END
  END vdd
  PIN vss
    DIRECTION INOUT ;
    USE GROUND ;
    SHAPE ABUTMENT ;
    PORT
      LAYER METAL1 ;
        POLYGON 0.000 1.100 64.800 1.100 64.800 3.700 59.600 3.700 59.600 19.200 57.000 19.200 57.000 3.700 47.500 3.700 47.500 19.200 42.900 19.200 42.900 3.700 25.500 3.700 25.500 13.400 29.500 13.400 29.500 19.200 26.900 19.200 26.900 15.200 15.300 15.200 15.300 19.200 12.700 19.200 12.700 13.400 22.900 13.400 22.900 3.700 7.300 3.700 7.300 19.200 4.700 19.200 4.700 3.700 0.000 3.700 ;
    END
  END vss
  OBS
    LAYER METAL1 ;
      POLYGON 7.300 49.300 3.300 49.300 3.300 55.700 0.700 55.700 0.700 47.500 4.700 47.500 4.700 37.500 7.300 37.500 ;
      POLYGON 51.500 54.200 48.900 54.200 48.900 36.900 49.700 36.900 49.700 31.300 51.500 31.300 ;
      RECT 9.800 50.900 12.800 53.500 ;
      RECT 61.000 31.300 63.600 48.400 ;
      POLYGON 21.500 27.700 23.200 27.700 23.200 30.300 21.500 30.300 21.500 41.500 18.900 41.500 18.900 36.900 19.700 36.900 19.700 19.200 18.900 19.200 18.900 16.600 21.500 16.600 ;
      POLYGON 25.500 20.600 27.400 20.600 27.400 35.500 25.500 35.500 25.500 41.500 22.900 41.500 22.900 36.900 23.700 36.900 23.700 33.700 25.600 33.700 25.600 22.400 23.700 22.400 23.700 19.200 22.900 19.200 22.900 16.600 25.500 16.600 ;
      POLYGON 41.500 20.600 43.400 20.600 43.400 35.500 41.500 35.500 41.500 41.500 38.900 41.500 38.900 36.900 39.700 36.900 39.700 33.700 41.600 33.700 41.600 22.400 39.700 22.400 39.700 19.200 38.900 19.200 38.900 16.600 41.500 16.600 ;
      RECT 12.600 25.100 15.200 27.900 ;
      RECT 55.000 25.100 57.600 27.900 ;
      POLYGON 51.200 20.600 51.200 11.200 53.800 11.200 53.800 19.200 53.000 19.200 53.000 22.400 51.600 22.400 51.600 27.900 49.800 27.900 49.800 20.600 ;
      RECT 61.000 16.600 63.600 27.900 ;
  END
END DFFRB

MACRO DFFS
  CLASS CORE ;
  FOREIGN DFFS -0.000 -0.000 ;
  ORIGIN 0.000 0.000 ;
  SIZE 64.800 BY 59.400 ;
  SITE TR1UM ;
  SYMMETRY X Y ;
  PIN CK
    DIRECTION INOUT ;
    USE SIGNAL ;
    PORT
      LAYER METAL2 ;
        RECT 6.400 50.900 9.800 54.300 ;
    END
  END CK
  PIN CKB
    DIRECTION INOUT ;
    USE SIGNAL ;
    PORT
      LAYER METAL1 ;
        POLYGON 3.300 19.200 2.500 19.200 2.500 37.500 3.300 37.500 3.300 46.100 0.700 46.100 0.700 11.200 3.300 11.200 ;
    END
  END CKB
  PIN CKP
    DIRECTION INOUT ;
    USE SIGNAL ;
    PORT
      LAYER METAL1 ;
        POLYGON 11.300 19.200 10.500 19.200 10.500 22.400 8.600 22.400 8.600 34.300 10.500 34.300 10.500 37.500 11.300 37.500 11.300 46.100 18.700 46.100 18.700 48.700 16.100 48.700 16.100 47.900 8.700 47.900 8.700 36.100 6.800 36.100 6.800 20.600 8.700 20.600 8.700 9.000 11.300 9.000 ;
    END
  END CKP
  PIN D
    DIRECTION INOUT ;
    USE SIGNAL ;
    PORT
      LAYER METAL2 ;
        RECT 11.800 27.900 15.200 31.300 ;
    END
  END D
  PIN Q
    DIRECTION INOUT ;
    USE SIGNAL ;
    PORT
      LAYER METAL2 ;
        RECT 60.400 27.900 63.800 31.300 ;
    END
  END Q
  PIN QB
    DIRECTION INOUT ;
    USE SIGNAL ;
    PORT
      LAYER METAL2 ;
        RECT 49.600 27.900 53.000 31.300 ;
        RECT 49.600 27.900 53.000 31.300 ;
    END
  END QB
  PIN QM
    DIRECTION INOUT ;
    USE SIGNAL ;
    PORT
      LAYER METAL1 ;
        POLYGON 29.500 10.200 33.500 10.200 33.500 19.200 32.700 19.200 32.700 22.400 30.600 22.400 30.600 33.700 32.700 33.700 32.700 36.900 33.500 36.900 33.500 47.900 29.500 47.900 29.500 48.700 26.900 48.700 26.900 46.100 30.900 46.100 30.900 35.500 28.800 35.500 28.800 20.600 30.900 20.600 30.900 12.000 26.900 12.000 26.900 9.400 29.500 9.400 ;
    END
  END QM
  PIN QS
    DIRECTION INOUT ;
    USE SIGNAL ;
    PORT
      LAYER METAL1 ;
        POLYGON 37.500 27.700 39.300 27.700 39.300 30.300 37.500 30.300 37.500 41.500 34.900 41.500 34.900 36.900 35.700 36.900 35.700 19.200 34.900 19.200 34.900 16.600 37.500 16.600 ;
    END
  END QS
  PIN SET
    DIRECTION INOUT ;
    USE SIGNAL ;
    PORT
      LAYER METAL2 ;
        RECT 55.000 27.900 58.400 31.300 ;
    END
  END SET
  PIN vdd
    DIRECTION INOUT ;
    USE POWER ;
    SHAPE ABUTMENT ;
    PORT
      LAYER METAL1 ;
        POLYGON 57.000 36.900 59.600 36.900 59.600 55.700 64.800 55.700 64.800 58.300 0.000 58.300 0.000 55.700 22.900 55.700 22.900 44.700 12.700 44.700 12.700 36.900 15.300 36.900 15.300 42.900 26.900 42.900 26.900 36.900 29.500 36.900 29.500 44.700 25.500 44.700 25.500 55.700 42.900 55.700 42.900 36.900 47.500 36.900 47.500 55.700 57.000 55.700 ;
    END
  END vdd
  PIN vss
    DIRECTION INOUT ;
    USE GROUND ;
    SHAPE ABUTMENT ;
    PORT
      LAYER METAL1 ;
        POLYGON 25.500 13.400 29.500 13.400 29.500 19.200 26.900 19.200 26.900 15.200 15.300 15.200 15.300 19.200 12.700 19.200 12.700 13.400 22.900 13.400 22.900 3.700 7.300 3.700 7.300 19.200 4.700 19.200 4.700 3.700 0.000 3.700 0.000 1.100 64.800 1.100 64.800 3.700 59.600 3.700 59.600 19.200 52.900 19.200 52.900 16.600 57.000 16.600 57.000 3.700 47.500 3.700 47.500 19.200 42.900 19.200 42.900 3.700 25.500 3.700 ;
    END
  END vss
  OBS
    LAYER METAL1 ;
      POLYGON 7.300 37.500 7.300 49.300 3.300 49.300 3.300 55.700 0.700 55.700 0.700 47.500 4.700 47.500 4.700 37.500 ;
      POLYGON 52.900 36.900 53.700 36.900 53.700 54.300 51.100 54.300 51.100 31.300 52.900 31.300 ;
      RECT 9.800 50.900 12.800 53.500 ;
      RECT 61.000 31.300 63.600 48.400 ;
      POLYGON 21.500 27.700 23.200 27.700 23.200 30.300 21.500 30.300 21.500 41.500 18.900 41.500 18.900 36.900 19.700 36.900 19.700 19.200 18.900 19.200 18.900 16.600 21.500 16.600 ;
      POLYGON 25.500 20.600 27.400 20.600 27.400 35.500 25.500 35.500 25.500 41.500 22.900 41.500 22.900 36.900 23.700 36.900 23.700 33.700 25.600 33.700 25.600 22.400 23.700 22.400 23.700 19.200 22.900 19.200 22.900 16.600 25.500 16.600 ;
      POLYGON 41.500 20.600 43.400 20.600 43.400 35.500 41.500 35.500 41.500 41.500 38.900 41.500 38.900 36.900 39.700 36.900 39.700 33.700 41.600 33.700 41.600 22.400 39.700 22.400 39.700 19.200 38.900 19.200 38.900 16.600 41.500 16.600 ;
      RECT 55.000 25.100 57.600 27.900 ;
      RECT 12.600 25.100 15.200 27.900 ;
      RECT 61.000 16.600 63.600 27.900 ;
      POLYGON 48.900 19.200 48.900 11.200 51.500 11.200 51.500 27.900 49.700 27.900 49.700 19.200 ;
  END
END DFFS

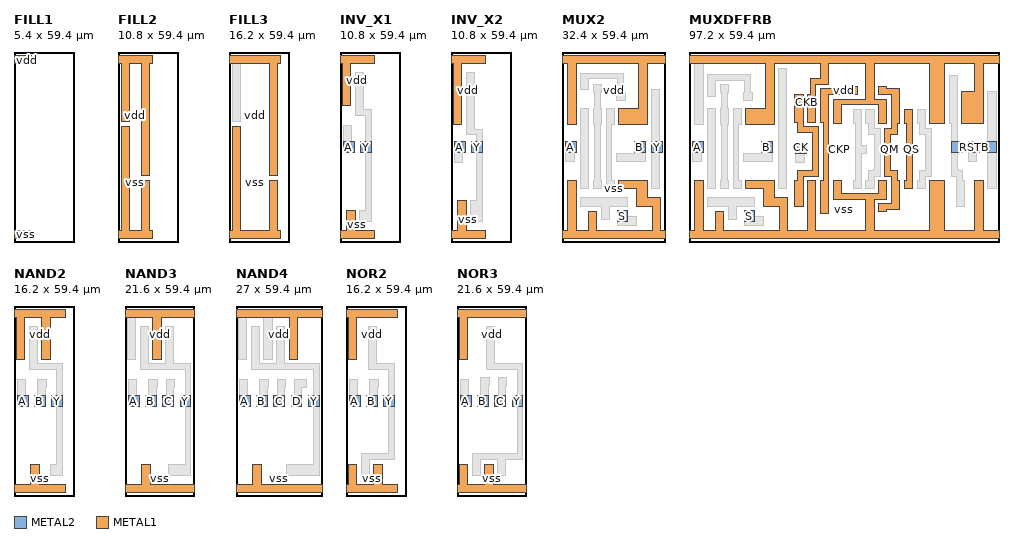
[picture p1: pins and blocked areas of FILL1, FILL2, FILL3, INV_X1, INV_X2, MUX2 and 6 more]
MACRO FILL1
  CLASS CORE SPACER ;
  FOREIGN FILL1 -0.000 -0.000 ;
  ORIGIN 0.000 0.000 ;
  SIZE 5.400 BY 59.400 ;
  SITE TR1UM ;
  SYMMETRY X Y ;
  PIN vdd
    DIRECTION INOUT ;
    USE POWER ;
    SHAPE ABUTMENT ;
    PORT
      LAYER METAL1 ;
        RECT 0.000 55.700 5.400 58.300 ;
    END
  END vdd
  PIN vss
    DIRECTION INOUT ;
    USE GROUND ;
    SHAPE ABUTMENT ;
    PORT
      LAYER METAL1 ;
        RECT 0.000 1.100 5.400 3.700 ;
    END
  END vss
END FILL1

MACRO FILL2
  CLASS CORE SPACER ;
  FOREIGN FILL2 -0.000 -0.000 ;
  ORIGIN 0.000 0.000 ;
  SIZE 10.800 BY 59.400 ;
  SITE TR1UM ;
  SYMMETRY X Y ;
  PIN vdd
    DIRECTION INOUT ;
    USE POWER ;
    SHAPE ABUTMENT ;
    PORT
      LAYER METAL1 ;
        POLYGON 3.600 37.700 3.600 55.700 7.200 55.700 7.200 20.700 9.800 20.700 9.800 55.700 10.800 55.700 10.800 58.300 0.000 58.300 0.000 55.700 1.000 55.700 1.000 37.700 ;
    END
  END vdd
  PIN vss
    DIRECTION INOUT ;
    USE GROUND ;
    SHAPE ABUTMENT ;
    PORT
      LAYER METAL1 ;
        POLYGON 0.000 1.100 10.800 1.100 10.800 3.700 9.800 3.700 9.800 19.100 7.200 19.100 7.200 3.700 3.600 3.700 3.600 36.100 1.000 36.100 1.000 3.700 0.000 3.700 ;
    END
  END vss
END FILL2

MACRO FILL3
  CLASS CORE SPACER ;
  FOREIGN FILL3 -0.000 -0.000 ;
  ORIGIN 0.000 0.000 ;
  SIZE 16.200 BY 59.400 ;
  SITE TR1UM ;
  SYMMETRY X Y ;
  PIN vdd
    DIRECTION INOUT ;
    USE POWER ;
    SHAPE ABUTMENT ;
    PORT
      LAYER METAL1 ;
        POLYGON 15.200 20.700 15.200 55.700 16.200 55.700 16.200 58.300 0.000 58.300 0.000 55.700 12.600 55.700 12.600 20.700 ;
    END
  END vdd
  PIN vss
    DIRECTION INOUT ;
    USE GROUND ;
    SHAPE ABUTMENT ;
    PORT
      LAYER METAL1 ;
        POLYGON 0.000 1.100 16.200 1.100 16.200 3.700 15.200 3.700 15.200 19.100 12.600 19.100 12.600 3.700 3.600 3.700 3.600 36.100 1.000 36.100 1.000 3.700 0.000 3.700 ;
    END
  END vss
  OBS
    LAYER METAL1 ;
      RECT 1.000 37.700 3.600 55.700 ;
  END
END FILL3

MACRO INV_X1
  CLASS CORE ;
  FOREIGN INV_X1 -0.000 -0.000 ;
  ORIGIN 0.000 0.000 ;
  SIZE 10.800 BY 59.400 ;
  SITE TR1UM ;
  SYMMETRY X Y ;
  PIN A
    DIRECTION INOUT ;
    USE SIGNAL ;
    PORT
      LAYER METAL2 ;
        RECT 1.000 28.000 4.400 31.400 ;
    END
  END A
  PIN Y
    DIRECTION INOUT ;
    USE SIGNAL ;
    PORT
      LAYER METAL2 ;
        RECT 6.400 28.000 9.800 31.400 ;
    END
  END Y
  PIN vdd
    DIRECTION INOUT ;
    USE POWER ;
    SHAPE ABUTMENT ;
    PORT
      LAYER METAL1 ;
        POLYGON 3.300 42.700 3.300 55.700 10.800 55.700 10.800 58.300 0.000 58.300 0.000 55.700 0.700 55.700 0.700 42.700 ;
    END
  END vdd
  PIN vss
    DIRECTION INOUT ;
    USE GROUND ;
    SHAPE ABUTMENT ;
    PORT
      LAYER METAL1 ;
        POLYGON 0.000 1.100 10.800 1.100 10.800 3.700 4.700 3.700 4.700 9.900 2.100 9.900 2.100 3.700 0.000 3.700 ;
    END
  END vss
  OBS
    LAYER METAL1 ;
      POLYGON 8.000 9.900 6.100 9.900 6.100 6.500 9.800 6.500 9.800 28.000 8.000 28.000 ;
      RECT 1.000 31.400 3.600 36.500 ;
      POLYGON 9.800 41.300 7.300 41.300 7.300 52.900 4.700 52.900 4.700 39.500 8.000 39.500 8.000 31.400 9.800 31.400 ;
  END
END INV_X1

MACRO INV_X2
  CLASS CORE ;
  FOREIGN INV_X2 -0.000 -0.000 ;
  ORIGIN 0.000 0.000 ;
  SIZE 10.800 BY 59.400 ;
  SITE TR1UM ;
  SYMMETRY X Y ;
  PIN A
    DIRECTION INOUT ;
    USE SIGNAL ;
    PORT
      LAYER METAL2 ;
        RECT 1.000 28.000 4.400 31.400 ;
    END
  END A
  PIN Y
    DIRECTION INOUT ;
    USE SIGNAL ;
    PORT
      LAYER METAL2 ;
        RECT 6.400 28.000 9.800 31.400 ;
    END
  END Y
  PIN vdd
    DIRECTION INOUT ;
    USE POWER ;
    SHAPE ABUTMENT ;
    PORT
      LAYER METAL1 ;
        POLYGON 3.300 36.700 3.300 55.700 10.800 55.700 10.800 58.300 0.000 58.300 0.000 55.700 0.700 55.700 0.700 36.700 ;
    END
  END vdd
  PIN vss
    DIRECTION INOUT ;
    USE GROUND ;
    SHAPE ABUTMENT ;
    PORT
      LAYER METAL1 ;
        POLYGON 0.000 1.100 10.800 1.100 10.800 3.700 4.700 3.700 4.700 13.100 2.100 13.100 2.100 3.700 0.000 3.700 ;
    END
  END vss
  OBS
    LAYER METAL1 ;
      POLYGON 9.800 35.300 7.300 35.300 7.300 52.900 4.700 52.900 4.700 33.500 8.000 33.500 8.000 31.400 9.800 31.400 ;
      RECT 1.000 25.000 3.600 28.000 ;
      POLYGON 6.100 13.100 6.100 6.500 9.800 6.500 9.800 28.000 8.000 28.000 8.000 13.100 ;
  END
END INV_X2

MACRO MUX2
  CLASS CORE ;
  FOREIGN MUX2 -0.000 -0.000 ;
  ORIGIN 0.000 0.000 ;
  SIZE 32.400 BY 59.400 ;
  SITE TR1UM ;
  SYMMETRY X Y ;
  PIN A
    DIRECTION INOUT ;
    USE SIGNAL ;
    PORT
      LAYER METAL2 ;
        RECT 1.000 27.900 4.400 31.300 ;
    END
  END A
  PIN B
    DIRECTION INOUT ;
    USE SIGNAL ;
    PORT
      LAYER METAL2 ;
        RECT 22.600 27.900 26.000 31.300 ;
    END
  END B
  PIN S
    DIRECTION INOUT ;
    USE SIGNAL ;
    PORT
      LAYER METAL2 ;
        RECT 17.200 6.300 20.600 9.700 ;
    END
  END S
  PIN Y
    DIRECTION INOUT ;
    USE SIGNAL ;
    PORT
      LAYER METAL2 ;
        RECT 28.000 27.900 31.400 31.300 ;
    END
  END Y
  PIN vdd
    DIRECTION INOUT ;
    USE POWER ;
    SHAPE ABUTMENT ;
    PORT
      LAYER METAL1 ;
        POLYGON 4.400 36.700 4.400 55.700 24.000 55.700 24.000 41.700 17.800 41.700 17.800 36.700 26.600 36.700 26.600 55.700 32.400 55.700 32.400 58.300 0.000 58.300 0.000 55.700 1.800 55.700 1.800 36.700 ;
    END
  END vdd
  PIN vss
    DIRECTION INOUT ;
    USE GROUND ;
    SHAPE ABUTMENT ;
    PORT
      LAYER METAL1 ;
        POLYGON 0.000 1.100 32.400 1.100 32.400 3.700 30.800 3.700 30.800 13.800 26.600 13.800 26.600 19.300 17.800 19.300 17.800 16.600 23.300 16.600 23.300 11.200 28.200 11.200 28.200 3.700 10.800 3.700 10.800 9.500 8.200 9.500 8.200 3.700 4.400 3.700 4.400 19.300 1.800 19.300 1.800 3.700 0.000 3.700 ;
    END
  END vss
  OBS
    LAYER METAL1 ;
      POLYGON 19.700 46.800 19.300 46.800 19.300 52.800 5.800 52.800 5.800 47.800 8.400 47.800 8.400 51.000 17.500 51.000 17.500 46.800 17.100 46.800 17.100 44.200 19.700 44.200 ;
      POLYGON 12.400 19.300 12.000 19.300 12.000 36.700 12.400 36.700 12.400 41.700 12.000 41.700 12.000 46.600 12.400 46.600 12.400 49.200 9.800 49.200 9.800 46.600 10.200 46.600 10.200 41.700 9.800 41.700 9.800 36.700 10.200 36.700 10.200 19.300 9.800 19.300 9.800 16.600 12.400 16.600 ;
      RECT 28.000 31.300 30.600 47.600 ;
      RECT 5.800 16.600 8.400 41.700 ;
      POLYGON 16.400 19.300 15.600 19.300 15.600 36.700 16.400 36.700 16.400 41.700 13.800 41.700 13.800 16.600 16.400 16.600 ;
      POLYGON 26.000 27.900 22.600 27.900 22.600 27.700 17.000 27.700 17.000 25.100 26.000 25.100 ;
      RECT 1.200 25.100 3.800 27.900 ;
      POLYGON 14.800 11.200 20.400 11.200 20.400 13.800 5.800 13.800 5.800 11.200 12.200 11.200 12.200 6.900 14.800 6.900 ;
      POLYGON 17.200 6.300 17.200 5.300 23.400 5.300 23.400 7.900 20.600 7.900 20.600 6.300 ;
      RECT 28.000 16.600 30.600 27.900 ;
  END
END MUX2

MACRO MUXDFFRB
  CLASS CORE ;
  FOREIGN MUXDFFRB -0.000 -0.000 ;
  ORIGIN 0.000 0.000 ;
  SIZE 97.200 BY 59.400 ;
  SITE TR1UM ;
  SYMMETRY X Y ;
  PIN A
    DIRECTION INOUT ;
    USE SIGNAL ;
    PORT
      LAYER METAL2 ;
        RECT 1.000 27.900 4.400 31.300 ;
    END
  END A
  PIN B
    DIRECTION INOUT ;
    USE SIGNAL ;
    PORT
      LAYER METAL2 ;
        RECT 22.600 27.900 26.000 31.300 ;
    END
  END B
  PIN CK
    DIRECTION INOUT ;
    USE SIGNAL ;
    PORT
      LAYER METAL2 ;
        RECT 33.400 27.700 36.800 31.100 ;
    END
  END CK
  PIN CKB
    DIRECTION INOUT ;
    USE SIGNAL ;
    PORT
      LAYER METAL1 ;
        POLYGON 33.900 34.300 38.700 34.300 38.700 22.400 33.900 22.400 33.900 19.200 33.100 19.200 33.100 11.200 35.700 11.200 35.700 20.600 40.500 20.600 40.500 36.100 35.700 36.100 35.700 46.100 33.100 46.100 33.100 37.500 33.900 37.500 ;
    END
  END CKB
  PIN CKP
    DIRECTION INOUT ;
    USE SIGNAL ;
    PORT
      LAYER METAL1 ;
        POLYGON 41.900 19.200 41.100 19.200 41.100 9.000 43.700 9.000 43.700 46.100 52.700 46.100 52.700 48.700 50.100 48.700 50.100 47.900 41.100 47.900 41.100 37.500 41.900 37.500 ;
    END
  END CKP
  PIN Q
    DIRECTION INOUT ;
    USE SIGNAL ;
    PORT
      LAYER METAL2 ;
        RECT 92.800 27.900 96.200 31.300 ;
    END
  END Q
  PIN QB
    DIRECTION INOUT ;
    USE SIGNAL ;
    PORT
      LAYER METAL2 ;
        RECT 82.000 27.900 85.400 31.300 ;
        RECT 82.000 27.900 85.400 31.300 ;
    END
  END QB
  PIN QM
    DIRECTION INOUT ;
    USE SIGNAL ;
    PORT
      LAYER METAL1 ;
        POLYGON 61.900 10.200 65.900 10.200 65.900 19.200 65.100 19.200 65.100 22.400 63.000 22.400 63.000 33.700 65.100 33.700 65.100 36.900 65.900 36.900 65.900 47.900 61.900 47.900 61.900 48.700 59.300 48.700 59.300 46.100 63.300 46.100 63.300 35.500 61.200 35.500 61.200 20.600 63.300 20.600 63.300 12.000 59.300 12.000 59.300 9.400 61.900 9.400 ;
    END
  END QM
  PIN QS
    DIRECTION INOUT ;
    USE SIGNAL ;
    PORT
      LAYER METAL1 ;
        POLYGON 69.900 27.700 71.700 27.700 71.700 30.300 69.900 30.300 69.900 41.500 67.300 41.500 67.300 36.900 68.100 36.900 68.100 19.200 67.300 19.200 67.300 16.600 69.900 16.600 ;
    END
  END QS
  PIN RSTB
    DIRECTION INOUT ;
    USE SIGNAL ;
    PORT
      LAYER METAL2 ;
        RECT 87.400 27.900 90.800 31.300 ;
    END
  END RSTB
  PIN S
    DIRECTION INOUT ;
    USE SIGNAL ;
    PORT
      LAYER METAL2 ;
        RECT 17.200 6.300 20.600 9.700 ;
    END
  END S
  PIN vdd
    DIRECTION INOUT ;
    USE POWER ;
    SHAPE ABUTMENT ;
    PORT
      LAYER METAL1 ;
        POLYGON 55.300 44.700 45.100 44.700 45.100 36.900 47.700 36.900 47.700 42.900 59.300 42.900 59.300 36.900 61.900 36.900 61.900 44.700 57.900 44.700 57.900 55.700 75.300 55.700 75.300 36.900 79.900 36.900 79.900 55.700 89.400 55.700 89.400 47.000 85.300 47.000 85.300 36.900 92.000 36.900 92.000 55.700 97.200 55.700 97.200 58.300 0.000 58.300 0.000 55.700 24.000 55.700 24.000 41.700 17.800 41.700 17.800 36.700 26.600 36.700 26.600 55.700 41.100 55.700 41.100 51.100 37.900 51.100 37.900 46.100 37.100 46.100 37.100 37.500 39.700 37.500 39.700 49.300 43.700 49.300 43.700 55.700 55.300 55.700 ;
    END
  END vdd
  PIN vss
    DIRECTION INOUT ;
    USE GROUND ;
    SHAPE ABUTMENT ;
    PORT
      LAYER METAL1 ;
        POLYGON 0.000 1.100 97.200 1.100 97.200 3.700 92.000 3.700 92.000 19.200 89.400 19.200 89.400 3.700 79.900 3.700 79.900 19.200 75.300 19.200 75.300 3.700 57.900 3.700 57.900 13.400 61.900 13.400 61.900 19.200 59.300 19.200 59.300 15.200 47.700 15.200 47.700 19.200 45.100 19.200 45.100 13.400 55.300 13.400 55.300 3.700 39.700 3.700 39.700 19.200 37.100 19.200 37.100 3.700 30.800 3.700 30.800 13.800 26.600 13.800 26.600 19.300 17.800 19.300 17.800 16.600 23.300 16.600 23.300 11.200 28.200 11.200 28.200 3.700 10.800 3.700 10.800 9.500 8.200 9.500 8.200 3.700 4.400 3.700 4.400 19.300 1.800 19.300 1.800 3.700 0.000 3.700 ;
    END
  END vss
  OBS
    LAYER METAL1 ;
      RECT 1.800 36.700 4.400 55.700 ;
      RECT 28.000 16.600 30.600 54.300 ;
      POLYGON 19.700 46.800 19.300 46.800 19.300 52.400 5.800 52.400 5.800 45.600 8.400 45.600 8.400 50.600 17.500 50.600 17.500 46.800 17.100 46.800 17.100 44.200 19.700 44.200 ;
      POLYGON 83.900 52.000 81.300 52.000 81.300 36.900 82.100 36.900 82.100 31.300 83.900 31.300 ;
      POLYGON 12.400 19.300 12.000 19.300 12.000 36.700 12.400 36.700 12.400 41.700 12.000 41.700 12.000 46.600 12.400 46.600 12.400 49.200 9.800 49.200 9.800 46.600 10.200 46.600 10.200 41.700 9.800 41.700 9.800 36.700 10.200 36.700 10.200 19.300 9.800 19.300 9.800 16.600 12.400 16.600 ;
      RECT 93.400 31.300 96.000 47.000 ;
      POLYGON 16.400 19.300 15.600 19.300 15.600 36.700 16.400 36.700 16.400 41.700 13.800 41.700 13.800 16.600 16.400 16.600 ;
      RECT 5.800 16.600 8.400 41.700 ;
      POLYGON 53.900 27.700 55.600 27.700 55.600 30.300 53.900 30.300 53.900 41.500 51.300 41.500 51.300 36.900 52.100 36.900 52.100 19.200 51.300 19.200 51.300 16.600 53.900 16.600 ;
      POLYGON 57.900 20.600 59.800 20.600 59.800 35.500 57.900 35.500 57.900 41.500 55.300 41.500 55.300 36.900 56.100 36.900 56.100 33.700 58.000 33.700 58.000 22.400 56.100 22.400 56.100 19.200 55.300 19.200 55.300 16.600 57.900 16.600 ;
      POLYGON 73.900 20.600 75.800 20.600 75.800 35.500 73.900 35.500 73.900 41.500 71.300 41.500 71.300 36.900 72.100 36.900 72.100 33.700 74.000 33.700 74.000 22.400 72.100 22.400 72.100 19.200 71.300 19.200 71.300 16.600 73.900 16.600 ;
      RECT 87.400 25.100 90.000 27.900 ;
      POLYGON 26.000 27.900 22.600 27.900 22.600 27.700 17.000 27.700 17.000 25.100 26.000 25.100 ;
      RECT 1.200 25.100 3.800 27.900 ;
      RECT 33.400 24.700 36.000 27.700 ;
      POLYGON 14.800 11.200 20.400 11.200 20.400 13.800 5.800 13.800 5.800 11.200 12.200 11.200 12.200 6.900 14.800 6.900 ;
      POLYGON 17.200 6.300 17.200 5.300 23.400 5.300 23.400 7.900 20.600 7.900 20.600 6.300 ;
      RECT 93.400 16.600 96.000 27.900 ;
      POLYGON 83.600 20.600 83.600 11.200 86.200 11.200 86.200 19.200 85.400 19.200 85.400 22.400 84.000 22.400 84.000 27.900 82.200 27.900 82.200 20.600 ;
  END
END MUXDFFRB

MACRO NAND2
  CLASS CORE ;
  FOREIGN NAND2 -0.000 -0.000 ;
  ORIGIN 0.000 0.000 ;
  SIZE 16.200 BY 59.400 ;
  SITE TR1UM ;
  SYMMETRY X Y ;
  PIN A
    DIRECTION INOUT ;
    USE SIGNAL ;
    PORT
      LAYER METAL2 ;
        RECT 1.000 28.000 4.400 31.400 ;
    END
  END A
  PIN B
    DIRECTION INOUT ;
    USE SIGNAL ;
    PORT
      LAYER METAL2 ;
        RECT 6.400 28.000 9.800 31.400 ;
    END
  END B
  PIN Y
    DIRECTION INOUT ;
    USE SIGNAL ;
    PORT
      LAYER METAL2 ;
        RECT 11.800 28.000 15.200 31.400 ;
    END
  END Y
  PIN vdd
    DIRECTION INOUT ;
    USE POWER ;
    SHAPE ABUTMENT ;
    PORT
      LAYER METAL1 ;
        POLYGON 3.300 42.700 3.300 55.700 8.700 55.700 8.700 42.700 11.300 42.700 11.300 55.700 16.200 55.700 16.200 58.300 0.000 58.300 0.000 55.700 0.700 55.700 0.700 42.700 ;
    END
  END vdd
  PIN vss
    DIRECTION INOUT ;
    USE GROUND ;
    SHAPE ABUTMENT ;
    PORT
      LAYER METAL1 ;
        POLYGON 0.000 1.100 16.200 1.100 16.200 3.700 7.900 3.700 7.900 9.900 5.300 9.900 5.300 3.700 0.000 3.700 ;
    END
  END vss
  OBS
    LAYER METAL1 ;
      POLYGON 13.400 31.400 15.200 31.400 15.200 41.300 7.300 41.300 7.300 52.900 4.700 52.900 4.700 39.500 13.400 39.500 ;
      RECT 1.000 31.400 3.600 36.500 ;
      POLYGON 9.800 33.900 10.100 33.900 10.100 36.500 7.500 36.500 7.500 31.400 9.800 31.400 ;
      POLYGON 11.500 9.900 11.500 6.500 15.200 6.500 15.200 28.000 13.400 28.000 13.400 9.900 ;
  END
END NAND2

MACRO NAND3
  CLASS CORE ;
  FOREIGN NAND3 -0.000 -0.000 ;
  ORIGIN 0.000 0.000 ;
  SIZE 21.600 BY 59.400 ;
  SITE TR1UM ;
  SYMMETRY X Y ;
  PIN A
    DIRECTION INOUT ;
    USE SIGNAL ;
    PORT
      LAYER METAL2 ;
        RECT 1.000 28.000 4.400 31.400 ;
    END
  END A
  PIN B
    DIRECTION INOUT ;
    USE SIGNAL ;
    PORT
      LAYER METAL2 ;
        RECT 6.400 28.000 9.800 31.400 ;
    END
  END B
  PIN C
    DIRECTION INOUT ;
    USE SIGNAL ;
    PORT
      LAYER METAL2 ;
        RECT 11.800 28.000 15.200 31.400 ;
    END
  END C
  PIN Y
    DIRECTION INOUT ;
    USE SIGNAL ;
    PORT
      LAYER METAL2 ;
        RECT 17.200 28.000 20.600 31.400 ;
    END
  END Y
  PIN vdd
    DIRECTION INOUT ;
    USE POWER ;
    SHAPE ABUTMENT ;
    PORT
      LAYER METAL1 ;
        POLYGON 11.300 42.700 11.300 55.700 21.600 55.700 21.600 58.300 0.000 58.300 0.000 55.700 8.700 55.700 8.700 42.700 ;
    END
  END vdd
  PIN vss
    DIRECTION INOUT ;
    USE GROUND ;
    SHAPE ABUTMENT ;
    PORT
      LAYER METAL1 ;
        POLYGON 0.000 1.100 21.600 1.100 21.600 3.700 7.900 3.700 7.900 9.900 5.300 9.900 5.300 3.700 0.000 3.700 ;
    END
  END vss
  OBS
    LAYER METAL1 ;
      RECT 0.700 42.700 3.300 55.700 ;
      POLYGON 20.600 41.300 15.300 41.300 15.300 52.900 12.700 52.900 12.700 41.300 7.300 41.300 7.300 52.900 4.700 52.900 4.700 39.500 18.800 39.500 18.800 31.400 20.600 31.400 ;
      POLYGON 15.200 33.900 15.500 33.900 15.500 36.500 12.900 36.500 12.900 31.400 15.200 31.400 ;
      POLYGON 9.800 33.900 10.100 33.900 10.100 36.500 7.500 36.500 7.500 31.400 9.800 31.400 ;
      RECT 1.000 31.400 3.600 36.500 ;
      POLYGON 13.700 9.900 13.700 6.500 20.600 6.500 20.600 28.000 18.800 28.000 18.800 9.900 ;
  END
END NAND3

MACRO NAND4
  CLASS CORE ;
  FOREIGN NAND4 -0.000 -0.000 ;
  ORIGIN 0.000 0.000 ;
  SIZE 27.000 BY 59.400 ;
  SITE TR1UM ;
  SYMMETRY X Y ;
  PIN A
    DIRECTION INOUT ;
    USE SIGNAL ;
    PORT
      LAYER METAL2 ;
        RECT 1.000 28.000 4.400 31.400 ;
    END
  END A
  PIN B
    DIRECTION INOUT ;
    USE SIGNAL ;
    PORT
      LAYER METAL2 ;
        RECT 6.400 28.000 9.800 31.400 ;
    END
  END B
  PIN C
    DIRECTION INOUT ;
    USE SIGNAL ;
    PORT
      LAYER METAL2 ;
        RECT 11.800 28.000 15.200 31.400 ;
    END
  END C
  PIN D
    DIRECTION INOUT ;
    USE SIGNAL ;
    PORT
      LAYER METAL2 ;
        RECT 17.200 28.000 20.600 31.400 ;
    END
  END D
  PIN Y
    DIRECTION INOUT ;
    USE SIGNAL ;
    PORT
      LAYER METAL2 ;
        RECT 22.600 28.000 26.000 31.400 ;
    END
  END Y
  PIN vdd
    DIRECTION INOUT ;
    USE POWER ;
    SHAPE ABUTMENT ;
    PORT
      LAYER METAL1 ;
        POLYGON 19.300 42.700 19.300 55.700 27.000 55.700 27.000 58.300 0.000 58.300 0.000 55.700 16.700 55.700 16.700 42.700 ;
    END
  END vdd
  PIN vss
    DIRECTION INOUT ;
    USE GROUND ;
    SHAPE ABUTMENT ;
    PORT
      LAYER METAL1 ;
        POLYGON 0.000 1.100 27.000 1.100 27.000 3.700 7.900 3.700 7.900 9.900 5.300 9.900 5.300 3.700 0.000 3.700 ;
    END
  END vss
  OBS
    LAYER METAL1 ;
      RECT 0.700 42.700 3.300 55.700 ;
      RECT 8.700 42.700 11.300 55.700 ;
      POLYGON 26.000 41.300 15.300 41.300 15.300 52.900 12.700 52.900 12.700 41.300 7.300 41.300 7.300 52.900 4.700 52.900 4.700 39.500 24.200 39.500 24.200 31.400 26.000 31.400 ;
      POLYGON 15.200 33.900 15.500 33.900 15.500 36.500 12.900 36.500 12.900 31.400 15.200 31.400 ;
      RECT 1.000 31.400 3.600 36.500 ;
      POLYGON 9.800 33.900 10.100 33.900 10.100 36.500 7.500 36.500 7.500 31.400 9.800 31.400 ;
      POLYGON 20.600 33.900 22.100 33.900 22.100 36.500 18.300 36.500 18.300 31.400 20.600 31.400 ;
      POLYGON 15.900 9.900 15.900 6.500 26.000 6.500 26.000 28.000 24.200 28.000 24.200 9.900 ;
  END
END NAND4

MACRO NOR2
  CLASS CORE ;
  FOREIGN NOR2 -0.000 -0.000 ;
  ORIGIN 0.000 0.000 ;
  SIZE 16.200 BY 59.400 ;
  SITE TR1UM ;
  SYMMETRY X Y ;
  PIN A
    DIRECTION INOUT ;
    USE SIGNAL ;
    PORT
      LAYER METAL2 ;
        RECT 1.000 28.000 4.400 31.400 ;
    END
  END A
  PIN B
    DIRECTION INOUT ;
    USE SIGNAL ;
    PORT
      LAYER METAL2 ;
        RECT 6.400 28.000 9.800 31.400 ;
    END
  END B
  PIN Y
    DIRECTION INOUT ;
    USE SIGNAL ;
    PORT
      LAYER METAL2 ;
        RECT 11.800 28.000 15.200 31.400 ;
    END
  END Y
  PIN vdd
    DIRECTION INOUT ;
    USE POWER ;
    SHAPE ABUTMENT ;
    PORT
      LAYER METAL1 ;
        POLYGON 3.300 42.700 3.300 55.700 16.200 55.700 16.200 58.300 0.000 58.300 0.000 55.700 0.700 55.700 0.700 42.700 ;
    END
  END vdd
  PIN vss
    DIRECTION INOUT ;
    USE GROUND ;
    SHAPE ABUTMENT ;
    PORT
      LAYER METAL1 ;
        POLYGON 0.000 1.100 16.200 1.100 16.200 3.700 11.300 3.700 11.300 9.900 8.700 9.900 8.700 3.700 3.300 3.700 3.300 9.900 0.700 9.900 0.700 3.700 0.000 3.700 ;
    END
  END vss
  OBS
    LAYER METAL1 ;
      POLYGON 15.200 41.300 9.500 41.300 9.500 52.900 6.900 52.900 6.900 39.500 13.400 39.500 13.400 31.400 15.200 31.400 ;
      RECT 1.000 31.400 3.600 36.500 ;
      POLYGON 9.800 33.900 10.100 33.900 10.100 36.500 7.500 36.500 7.500 31.400 9.800 31.400 ;
      POLYGON 4.700 13.200 4.700 6.500 7.300 6.500 7.300 11.400 15.200 11.400 15.200 28.000 13.400 28.000 13.400 13.200 ;
  END
END NOR2

MACRO NOR3
  CLASS CORE ;
  FOREIGN NOR3 -0.000 -0.000 ;
  ORIGIN 0.000 0.000 ;
  SIZE 21.600 BY 59.400 ;
  SITE TR1UM ;
  SYMMETRY X Y ;
  PIN A
    DIRECTION INOUT ;
    USE SIGNAL ;
    PORT
      LAYER METAL2 ;
        RECT 1.000 28.000 4.400 31.400 ;
    END
  END A
  PIN B
    DIRECTION INOUT ;
    USE SIGNAL ;
    PORT
      LAYER METAL2 ;
        RECT 6.400 28.000 9.800 31.400 ;
    END
  END B
  PIN C
    DIRECTION INOUT ;
    USE SIGNAL ;
    PORT
      LAYER METAL2 ;
        RECT 11.800 28.000 15.200 31.400 ;
    END
  END C
  PIN Y
    DIRECTION INOUT ;
    USE SIGNAL ;
    PORT
      LAYER METAL2 ;
        RECT 17.200 28.000 20.600 31.400 ;
    END
  END Y
  PIN vdd
    DIRECTION INOUT ;
    USE POWER ;
    SHAPE ABUTMENT ;
    PORT
      LAYER METAL1 ;
        POLYGON 3.300 42.700 3.300 55.700 21.600 55.700 21.600 58.300 0.000 58.300 0.000 55.700 0.700 55.700 0.700 42.700 ;
    END
  END vdd
  PIN vss
    DIRECTION INOUT ;
    USE GROUND ;
    SHAPE ABUTMENT ;
    PORT
      LAYER METAL1 ;
        POLYGON 0.000 1.100 21.600 1.100 21.600 3.700 11.300 3.700 11.300 9.900 8.700 9.900 8.700 3.700 3.300 3.700 3.300 9.900 0.700 9.900 0.700 3.700 0.000 3.700 ;
    END
  END vss
  OBS
    LAYER METAL1 ;
      POLYGON 20.600 41.300 11.700 41.300 11.700 52.900 9.100 52.900 9.100 39.500 18.800 39.500 18.800 31.400 20.600 31.400 ;
      POLYGON 9.800 34.500 10.100 34.500 10.100 37.100 7.500 37.100 7.500 31.400 9.800 31.400 ;
      POLYGON 15.200 34.400 15.500 34.400 15.500 37.000 12.900 37.000 12.900 31.400 15.200 31.400 ;
      RECT 1.000 31.400 3.600 36.500 ;
      POLYGON 4.700 13.200 4.700 6.500 7.300 6.500 7.300 11.400 12.700 11.400 12.700 6.500 15.300 6.500 15.300 11.400 20.600 11.400 20.600 28.000 18.800 28.000 18.800 13.200 ;
  END
END NOR3

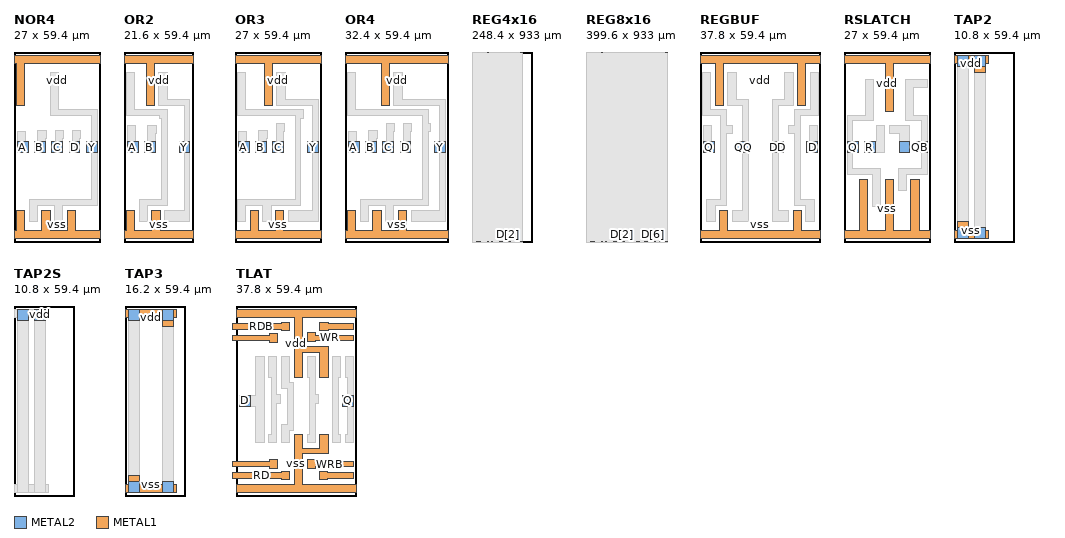
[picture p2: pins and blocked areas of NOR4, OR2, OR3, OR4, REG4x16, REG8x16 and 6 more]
MACRO NOR4
  CLASS CORE ;
  FOREIGN NOR4 -0.000 -0.000 ;
  ORIGIN 0.000 0.000 ;
  SIZE 27.000 BY 59.400 ;
  SITE TR1UM ;
  SYMMETRY X Y ;
  PIN A
    DIRECTION INOUT ;
    USE SIGNAL ;
    PORT
      LAYER METAL2 ;
        RECT 1.000 28.000 4.400 31.400 ;
    END
  END A
  PIN B
    DIRECTION INOUT ;
    USE SIGNAL ;
    PORT
      LAYER METAL2 ;
        RECT 6.400 28.000 9.800 31.400 ;
    END
  END B
  PIN C
    DIRECTION INOUT ;
    USE SIGNAL ;
    PORT
      LAYER METAL2 ;
        RECT 11.800 28.000 15.200 31.400 ;
    END
  END C
  PIN D
    DIRECTION INOUT ;
    USE SIGNAL ;
    PORT
      LAYER METAL2 ;
        RECT 17.200 28.000 20.600 31.400 ;
    END
  END D
  PIN Y
    DIRECTION INOUT ;
    USE SIGNAL ;
    PORT
      LAYER METAL2 ;
        RECT 22.600 28.000 26.000 31.400 ;
    END
  END Y
  PIN vdd
    DIRECTION INOUT ;
    USE POWER ;
    SHAPE ABUTMENT ;
    PORT
      LAYER METAL1 ;
        POLYGON 3.300 42.700 3.300 55.700 27.000 55.700 27.000 58.300 0.000 58.300 0.000 55.700 0.700 55.700 0.700 42.700 ;
    END
  END vdd
  PIN vss
    DIRECTION INOUT ;
    USE GROUND ;
    SHAPE ABUTMENT ;
    PORT
      LAYER METAL1 ;
        POLYGON 0.000 1.100 27.000 1.100 27.000 3.700 19.300 3.700 19.300 9.900 16.700 9.900 16.700 3.700 11.300 3.700 11.300 9.900 8.700 9.900 8.700 3.700 3.300 3.700 3.300 9.900 0.700 9.900 0.700 3.700 0.000 3.700 ;
    END
  END vss
  OBS
    LAYER METAL1 ;
      POLYGON 26.000 41.300 13.900 41.300 13.900 52.900 11.300 52.900 11.300 39.500 24.200 39.500 24.200 31.400 26.000 31.400 ;
      POLYGON 15.200 32.400 15.500 32.400 15.500 35.000 12.900 35.000 12.900 31.400 15.200 31.400 ;
      POLYGON 9.800 32.400 10.100 32.400 10.100 35.000 7.500 35.000 7.500 31.400 9.800 31.400 ;
      POLYGON 20.600 32.400 20.900 32.400 20.900 35.000 18.300 35.000 18.300 31.400 20.600 31.400 ;
      RECT 1.000 31.400 3.600 34.400 ;
      POLYGON 4.700 13.200 4.700 6.500 7.300 6.500 7.300 11.400 12.700 11.400 12.700 6.500 15.300 6.500 15.300 11.400 26.000 11.400 26.000 28.000 24.200 28.000 24.200 13.200 ;
  END
END NOR4

MACRO OR2
  CLASS CORE ;
  FOREIGN OR2 -0.000 -0.000 ;
  ORIGIN 0.000 0.000 ;
  SIZE 21.600 BY 59.400 ;
  SITE TR1UM ;
  SYMMETRY X Y ;
  PIN A
    DIRECTION INOUT ;
    USE SIGNAL ;
    PORT
      LAYER METAL2 ;
        RECT 1.000 28.000 4.400 31.400 ;
    END
  END A
  PIN B
    DIRECTION INOUT ;
    USE SIGNAL ;
    PORT
      LAYER METAL2 ;
        RECT 6.400 28.000 9.800 31.400 ;
    END
  END B
  PIN Y
    DIRECTION INOUT ;
    USE SIGNAL ;
    PORT
      LAYER METAL2 ;
        RECT 17.200 28.000 20.600 31.400 ;
        RECT 17.200 28.000 20.600 31.400 ;
    END
  END Y
  PIN vdd
    DIRECTION INOUT ;
    USE POWER ;
    SHAPE ABUTMENT ;
    PORT
      LAYER METAL1 ;
        POLYGON 9.500 42.700 9.500 55.700 21.600 55.700 21.600 58.300 0.000 58.300 0.000 55.700 6.900 55.700 6.900 42.700 ;
    END
  END vdd
  PIN vss
    DIRECTION INOUT ;
    USE GROUND ;
    SHAPE ABUTMENT ;
    PORT
      LAYER METAL1 ;
        POLYGON 0.000 1.100 21.600 1.100 21.600 3.700 11.300 3.700 11.300 9.900 8.700 9.900 8.700 3.700 3.300 3.700 3.300 9.900 0.700 9.900 0.700 3.700 0.000 3.700 ;
    END
  END vss
  OBS
    LAYER METAL1 ;
      POLYGON 7.300 11.400 13.600 11.400 13.600 41.300 3.300 41.300 3.300 52.900 0.700 52.900 0.700 39.500 11.000 39.500 11.000 38.700 11.800 38.700 11.800 13.200 4.700 13.200 4.700 6.500 7.300 6.500 ;
      POLYGON 10.900 52.900 10.900 42.700 18.800 42.700 18.800 31.400 20.600 31.400 20.600 44.500 13.500 44.500 13.500 52.900 ;
      RECT 1.000 31.400 3.600 36.500 ;
      POLYGON 9.800 33.900 10.100 33.900 10.100 36.500 7.500 36.500 7.500 31.400 9.800 31.400 ;
      POLYGON 20.600 28.000 18.800 28.000 18.800 9.900 12.700 9.900 12.700 6.500 20.600 6.500 ;
  END
END OR2

MACRO OR3
  CLASS CORE ;
  FOREIGN OR3 -0.000 -0.000 ;
  ORIGIN 0.000 0.000 ;
  SIZE 27.000 BY 59.400 ;
  SITE TR1UM ;
  SYMMETRY X Y ;
  PIN A
    DIRECTION INOUT ;
    USE SIGNAL ;
    PORT
      LAYER METAL2 ;
        RECT 1.000 28.000 4.400 31.400 ;
    END
  END A
  PIN B
    DIRECTION INOUT ;
    USE SIGNAL ;
    PORT
      LAYER METAL2 ;
        RECT 6.400 28.000 9.800 31.400 ;
    END
  END B
  PIN C
    DIRECTION INOUT ;
    USE SIGNAL ;
    PORT
      LAYER METAL2 ;
        RECT 11.800 28.000 15.200 31.400 ;
    END
  END C
  PIN Y
    DIRECTION INOUT ;
    USE SIGNAL ;
    PORT
      LAYER METAL2 ;
        RECT 22.600 28.000 26.000 31.400 ;
    END
  END Y
  PIN vdd
    DIRECTION INOUT ;
    USE POWER ;
    SHAPE ABUTMENT ;
    PORT
      LAYER METAL1 ;
        POLYGON 11.700 42.700 11.700 55.700 27.000 55.700 27.000 58.300 0.000 58.300 0.000 55.700 9.100 55.700 9.100 42.700 ;
    END
  END vdd
  PIN vss
    DIRECTION INOUT ;
    USE GROUND ;
    SHAPE ABUTMENT ;
    PORT
      LAYER METAL1 ;
        POLYGON 0.000 1.100 27.000 1.100 27.000 3.700 15.300 3.700 15.300 9.900 12.700 9.900 12.700 3.700 7.300 3.700 7.300 9.900 4.700 9.900 4.700 3.700 0.000 3.700 ;
    END
  END vss
  OBS
    LAYER METAL1 ;
      POLYGON 21.400 38.600 21.400 41.300 3.300 41.300 3.300 52.900 0.700 52.900 0.700 39.500 18.800 39.500 18.800 13.200 0.700 13.200 0.700 6.500 3.300 6.500 3.300 11.400 8.700 11.400 8.700 6.500 11.300 6.500 11.300 11.400 20.600 11.400 20.600 38.600 ;
      POLYGON 26.000 44.500 15.700 44.500 15.700 52.900 13.100 52.900 13.100 42.700 24.200 42.700 24.200 31.400 26.000 31.400 ;
      POLYGON 15.200 34.600 15.500 34.600 15.500 37.200 12.900 37.200 12.900 31.400 15.200 31.400 ;
      POLYGON 9.800 32.400 10.100 32.400 10.100 35.000 7.500 35.000 7.500 31.400 9.800 31.400 ;
      RECT 1.000 31.400 3.600 34.400 ;
      POLYGON 16.700 9.900 16.700 6.500 26.000 6.500 26.000 28.000 24.200 28.000 24.200 9.900 ;
  END
END OR3

MACRO OR4
  CLASS CORE ;
  FOREIGN OR4 -0.000 -0.000 ;
  ORIGIN 0.000 0.000 ;
  SIZE 32.400 BY 59.400 ;
  SITE TR1UM ;
  SYMMETRY X Y ;
  PIN A
    DIRECTION INOUT ;
    USE SIGNAL ;
    PORT
      LAYER METAL2 ;
        RECT 1.000 28.000 4.400 31.400 ;
    END
  END A
  PIN B
    DIRECTION INOUT ;
    USE SIGNAL ;
    PORT
      LAYER METAL2 ;
        RECT 6.400 28.000 9.800 31.400 ;
    END
  END B
  PIN C
    DIRECTION INOUT ;
    USE SIGNAL ;
    PORT
      LAYER METAL2 ;
        RECT 11.800 28.000 15.200 31.400 ;
    END
  END C
  PIN D
    DIRECTION INOUT ;
    USE SIGNAL ;
    PORT
      LAYER METAL2 ;
        RECT 17.200 28.000 20.600 31.400 ;
    END
  END D
  PIN Y
    DIRECTION INOUT ;
    USE SIGNAL ;
    PORT
      LAYER METAL2 ;
        RECT 28.000 28.000 31.400 31.400 ;
    END
  END Y
  PIN vdd
    DIRECTION INOUT ;
    USE POWER ;
    SHAPE ABUTMENT ;
    PORT
      LAYER METAL1 ;
        POLYGON 13.900 42.700 13.900 55.700 32.400 55.700 32.400 58.300 0.000 58.300 0.000 55.700 11.300 55.700 11.300 42.700 ;
    END
  END vdd
  PIN vss
    DIRECTION INOUT ;
    USE GROUND ;
    SHAPE ABUTMENT ;
    PORT
      LAYER METAL1 ;
        POLYGON 0.000 1.100 32.400 1.100 32.400 3.700 19.300 3.700 19.300 9.900 16.700 9.900 16.700 3.700 11.300 3.700 11.300 9.900 8.700 9.900 8.700 3.700 3.300 3.700 3.300 9.900 0.700 9.900 0.700 3.700 0.000 3.700 ;
    END
  END vss
  OBS
    LAYER METAL1 ;
      POLYGON 31.400 44.500 17.900 44.500 17.900 52.900 15.300 52.900 15.300 42.700 29.600 42.700 29.600 31.400 31.400 31.400 ;
      POLYGON 7.300 11.400 12.700 11.400 12.700 6.500 15.300 6.500 15.300 11.400 26.000 11.400 26.000 34.600 26.800 34.600 26.800 37.200 26.000 37.200 26.000 41.300 3.300 41.300 3.300 52.900 0.700 52.900 0.700 39.500 24.200 39.500 24.200 13.200 4.700 13.200 4.700 6.500 7.300 6.500 ;
      POLYGON 15.200 34.600 15.500 34.600 15.500 37.200 12.900 37.200 12.900 31.400 15.200 31.400 ;
      POLYGON 20.600 34.600 20.900 34.600 20.900 37.200 18.300 37.200 18.300 31.400 20.600 31.400 ;
      POLYGON 9.800 32.400 10.100 32.400 10.100 35.000 7.500 35.000 7.500 31.400 9.800 31.400 ;
      RECT 1.000 31.400 3.600 34.400 ;
      POLYGON 20.700 9.900 20.700 6.500 31.400 6.500 31.400 28.000 29.600 28.000 29.600 9.900 ;
  END
END OR4

MACRO REG4x16
  CLASS BLOCK ;
  FOREIGN REG4x16 -0.000 -0.000 ;
  ORIGIN 0.000 0.000 ;
  SIZE 248.400 BY 933.000 ;
  SYMMETRY X Y ;
  PIN ADD[0]
    DIRECTION INOUT ;
    USE SIGNAL ;
    PORT
      LAYER METAL2 ;
        RECT 22.600 1.100 26.000 4.500 ;
    END
  END ADD[0]
  PIN ADD[1]
    DIRECTION INOUT ;
    USE SIGNAL ;
    PORT
      LAYER METAL2 ;
        RECT 33.400 1.100 36.800 4.500 ;
    END
  END ADD[1]
  PIN ADD[2]
    DIRECTION INOUT ;
    USE SIGNAL ;
    PORT
      LAYER METAL2 ;
        RECT 38.800 1.100 42.200 4.500 ;
    END
  END ADD[2]
  PIN ADD[3]
    DIRECTION INOUT ;
    USE SIGNAL ;
    PORT
      LAYER METAL2 ;
        RECT 49.600 1.100 53.000 4.500 ;
    END
  END ADD[3]
  PIN D[0]
    DIRECTION INOUT ;
    USE SIGNAL ;
    PORT
      LAYER METAL2 ;
        RECT 98.200 1.100 101.600 4.500 ;
    END
  END D[0]
  PIN D[1]
    DIRECTION INOUT ;
    USE SIGNAL ;
    PORT
      LAYER METAL2 ;
        RECT 136.000 1.100 139.400 4.500 ;
    END
  END D[1]
  PIN D[2]
    DIRECTION INOUT ;
    USE SIGNAL ;
    PORT
      LAYER METAL2 ;
        RECT 173.800 1.100 177.200 4.500 ;
    END
  END D[2]
  PIN D[3]
    DIRECTION INOUT ;
    USE SIGNAL ;
    PORT
      LAYER METAL2 ;
        RECT 211.600 1.100 215.000 4.500 ;
    END
  END D[3]
  PIN Q[0]
    DIRECTION INOUT ;
    USE SIGNAL ;
    PORT
      LAYER METAL2 ;
        RECT 109.000 1.100 112.400 4.500 ;
    END
  END Q[0]
  PIN Q[1]
    DIRECTION INOUT ;
    USE SIGNAL ;
    PORT
      LAYER METAL2 ;
        RECT 146.800 1.100 150.200 4.500 ;
    END
  END Q[1]
  PIN Q[2]
    DIRECTION INOUT ;
    USE SIGNAL ;
    PORT
      LAYER METAL2 ;
        RECT 184.600 1.100 188.000 4.500 ;
    END
  END Q[2]
  PIN Q[3]
    DIRECTION INOUT ;
    USE SIGNAL ;
    PORT
      LAYER METAL2 ;
        RECT 222.400 1.100 225.800 4.500 ;
    END
  END Q[3]
  PIN WEB
    DIRECTION INOUT ;
    USE SIGNAL ;
    PORT
      LAYER METAL2 ;
        RECT 6.400 1.100 9.800 4.500 ;
    END
  END WEB
  PIN vdd
    DIRECTION INOUT ;
    USE POWER ;
    SHAPE ABUTMENT ;
    PORT
      LAYER METAL2 ;
        RECT 76.600 1.100 80.000 4.500 ;
        RECT 244.000 1.100 247.400 4.500 ;
        RECT 244.000 928.500 247.400 931.900 ;
        RECT 76.600 928.500 80.000 931.900 ;
    END
  END vdd
  PIN vss
    DIRECTION INOUT ;
    USE GROUND ;
    SHAPE ABUTMENT ;
    PORT
      LAYER METAL2 ;
        RECT 1.000 1.100 4.400 4.500 ;
        RECT 238.600 1.100 242.000 4.500 ;
        RECT 1.000 928.500 4.400 931.900 ;
        RECT 238.600 928.500 242.000 931.900 ;
    END
  END vss
  OBS
    LAYER METAL1 ;
      RECT 0.000 0.000 248.400 933.000 ;
    LAYER METAL2 ;
      RECT 0.000 0.000 248.400 933.000 ;
  END
END REG4x16

MACRO REG8x16
  CLASS BLOCK ;
  FOREIGN REG8x16 -0.000 -0.000 ;
  ORIGIN 0.000 0.000 ;
  SIZE 399.600 BY 933.000 ;
  SYMMETRY X Y ;
  PIN ADD[0]
    DIRECTION INOUT ;
    USE SIGNAL ;
    PORT
      LAYER METAL2 ;
        RECT 22.600 1.100 26.000 4.500 ;
    END
  END ADD[0]
  PIN ADD[1]
    DIRECTION INOUT ;
    USE SIGNAL ;
    PORT
      LAYER METAL2 ;
        RECT 33.400 1.100 36.800 4.500 ;
    END
  END ADD[1]
  PIN ADD[2]
    DIRECTION INOUT ;
    USE SIGNAL ;
    PORT
      LAYER METAL2 ;
        RECT 38.800 1.100 42.200 4.500 ;
    END
  END ADD[2]
  PIN ADD[3]
    DIRECTION INOUT ;
    USE SIGNAL ;
    PORT
      LAYER METAL2 ;
        RECT 49.600 1.100 53.000 4.500 ;
    END
  END ADD[3]
  PIN D[0]
    DIRECTION INOUT ;
    USE SIGNAL ;
    PORT
      LAYER METAL2 ;
        RECT 98.200 1.100 101.600 4.500 ;
    END
  END D[0]
  PIN D[1]
    DIRECTION INOUT ;
    USE SIGNAL ;
    PORT
      LAYER METAL2 ;
        RECT 136.000 1.100 139.400 4.500 ;
    END
  END D[1]
  PIN D[2]
    DIRECTION INOUT ;
    USE SIGNAL ;
    PORT
      LAYER METAL2 ;
        RECT 173.800 1.100 177.200 4.500 ;
    END
  END D[2]
  PIN D[3]
    DIRECTION INOUT ;
    USE SIGNAL ;
    PORT
      LAYER METAL2 ;
        RECT 211.600 1.100 215.000 4.500 ;
    END
  END D[3]
  PIN D[4]
    DIRECTION INOUT ;
    USE SIGNAL ;
    PORT
      LAYER METAL2 ;
        RECT 249.400 1.100 252.800 4.500 ;
    END
  END D[4]
  PIN D[5]
    DIRECTION INOUT ;
    USE SIGNAL ;
    PORT
      LAYER METAL2 ;
        RECT 287.200 1.100 290.600 4.500 ;
    END
  END D[5]
  PIN D[6]
    DIRECTION INOUT ;
    USE SIGNAL ;
    PORT
      LAYER METAL2 ;
        RECT 325.000 1.100 328.400 4.500 ;
    END
  END D[6]
  PIN D[7]
    DIRECTION INOUT ;
    USE SIGNAL ;
    PORT
      LAYER METAL2 ;
        RECT 362.800 1.100 366.200 4.500 ;
    END
  END D[7]
  PIN Q[0]
    DIRECTION INOUT ;
    USE SIGNAL ;
    PORT
      LAYER METAL2 ;
        RECT 109.000 1.100 112.400 4.500 ;
    END
  END Q[0]
  PIN Q[1]
    DIRECTION INOUT ;
    USE SIGNAL ;
    PORT
      LAYER METAL2 ;
        RECT 146.800 1.100 150.200 4.500 ;
    END
  END Q[1]
  PIN Q[2]
    DIRECTION INOUT ;
    USE SIGNAL ;
    PORT
      LAYER METAL2 ;
        RECT 184.600 1.100 188.000 4.500 ;
    END
  END Q[2]
  PIN Q[3]
    DIRECTION INOUT ;
    USE SIGNAL ;
    PORT
      LAYER METAL2 ;
        RECT 222.400 1.100 225.800 4.500 ;
    END
  END Q[3]
  PIN Q[4]
    DIRECTION INOUT ;
    USE SIGNAL ;
    PORT
      LAYER METAL2 ;
        RECT 260.200 1.100 263.600 4.500 ;
    END
  END Q[4]
  PIN Q[5]
    DIRECTION INOUT ;
    USE SIGNAL ;
    PORT
      LAYER METAL2 ;
        RECT 298.000 1.100 301.400 4.500 ;
    END
  END Q[5]
  PIN Q[6]
    DIRECTION INOUT ;
    USE SIGNAL ;
    PORT
      LAYER METAL2 ;
        RECT 335.800 1.100 339.200 4.500 ;
    END
  END Q[6]
  PIN Q[7]
    DIRECTION INOUT ;
    USE SIGNAL ;
    PORT
      LAYER METAL2 ;
        RECT 373.600 1.100 377.000 4.500 ;
    END
  END Q[7]
  PIN WEB
    DIRECTION INOUT ;
    USE SIGNAL ;
    PORT
      LAYER METAL2 ;
        RECT 6.400 1.100 9.800 4.500 ;
    END
  END WEB
  PIN vdd
    DIRECTION INOUT ;
    USE POWER ;
    SHAPE ABUTMENT ;
    PORT
      LAYER METAL2 ;
        RECT 395.200 1.100 398.600 4.500 ;
        RECT 395.200 928.500 398.600 931.900 ;
        RECT 76.600 1.100 80.000 4.500 ;
        RECT 76.600 928.500 80.000 931.900 ;
    END
  END vdd
  PIN vss
    DIRECTION INOUT ;
    USE GROUND ;
    SHAPE ABUTMENT ;
    PORT
      LAYER METAL2 ;
        RECT 389.800 1.100 393.200 4.500 ;
        RECT 389.800 928.500 393.200 931.900 ;
        RECT 1.000 1.100 4.400 4.500 ;
        RECT 1.000 928.500 4.400 931.900 ;
    END
  END vss
  OBS
    LAYER METAL1 ;
      RECT 0.000 0.000 399.600 933.000 ;
    LAYER METAL2 ;
      RECT 0.000 0.000 399.600 933.000 ;
  END
END REG8x16

MACRO REGBUF
  CLASS BLOCK ;
  FOREIGN REGBUF -0.000 -0.000 ;
  ORIGIN 0.000 0.000 ;
  SIZE 37.800 BY 59.400 ;
  SYMMETRY X Y ;
  PIN D
    DIRECTION INOUT ;
    USE SIGNAL ;
    PORT
      LAYER METAL2 ;
        RECT 33.400 28.000 36.800 31.400 ;
    END
  END D
  PIN DD
    DIRECTION INOUT ;
    USE SIGNAL ;
    PORT
      LAYER METAL2 ;
        RECT 22.600 28.000 26.000 31.400 ;
    END
  END DD
  PIN Q
    DIRECTION INOUT ;
    USE SIGNAL ;
    PORT
      LAYER METAL2 ;
        RECT 1.000 28.000 4.400 31.400 ;
    END
  END Q
  PIN QQ
    DIRECTION INOUT ;
    USE SIGNAL ;
    PORT
      LAYER METAL2 ;
        RECT 11.800 28.000 15.200 31.400 ;
    END
  END QQ
  PIN vdd
    DIRECTION INOUT ;
    USE POWER ;
    SHAPE ABUTMENT ;
    PORT
      LAYER METAL1 ;
        POLYGON 37.800 58.300 0.000 58.300 0.000 55.700 4.700 55.700 4.700 42.700 7.300 42.700 7.300 55.700 30.500 55.700 30.500 42.700 33.100 42.700 33.100 55.700 37.800 55.700 ;
    END
  END vdd
  PIN vss
    DIRECTION INOUT ;
    USE GROUND ;
    SHAPE ABUTMENT ;
    PORT
      LAYER METAL1 ;
        POLYGON 0.000 1.100 37.800 1.100 37.800 3.700 31.700 3.700 31.700 9.900 29.100 9.900 29.100 3.700 8.700 3.700 8.700 9.900 6.100 9.900 6.100 3.700 0.000 3.700 ;
    END
  END vss
  OBS
    LAYER METAL1 ;
      POLYGON 24.400 42.700 29.100 42.700 29.100 52.900 26.500 52.900 26.500 44.500 22.600 44.500 22.600 31.400 24.400 31.400 ;
      POLYGON 4.700 11.500 8.300 11.500 8.300 33.900 10.100 33.900 10.100 36.500 8.300 36.500 8.300 41.300 3.300 41.300 3.300 52.900 0.700 52.900 0.700 39.500 6.500 39.500 6.500 13.300 2.100 13.300 2.100 6.500 4.700 6.500 ;
      POLYGON 15.200 44.500 11.300 44.500 11.300 52.900 8.700 52.900 8.700 42.700 13.400 42.700 13.400 31.400 15.200 31.400 ;
      POLYGON 35.700 13.300 31.300 13.300 31.300 39.500 37.100 39.500 37.100 52.900 34.500 52.900 34.500 41.300 29.500 41.300 29.500 36.500 27.700 36.500 27.700 33.900 29.500 33.900 29.500 11.500 33.100 11.500 33.100 6.500 35.700 6.500 ;
      RECT 34.200 31.400 36.800 36.500 ;
      RECT 1.000 31.400 3.600 36.500 ;
      POLYGON 27.700 6.500 27.700 9.900 24.400 9.900 24.400 28.000 22.600 28.000 22.600 6.500 ;
      POLYGON 10.100 9.900 10.100 6.500 15.200 6.500 15.200 28.000 13.400 28.000 13.400 9.900 ;
  END
END REGBUF

MACRO REGBUF4
  CLASS BLOCK ;
  FOREIGN REGBUF4 10.800 -0.000 ;
  ORIGIN 0.000 0.000 ;
  SIZE 162.000 BY 59.400 ;
  SYMMETRY X Y ;
  # ★ ピン未定義: GDS のトップにラベル/(49,1) 形状を入れて再生成すること
  OBS
    LAYER METAL1 ;
      RECT 0.000 0.000 162.000 59.400 ;
    LAYER METAL2 ;
      RECT 0.000 0.000 162.000 59.400 ;
  END
END REGBUF4

MACRO REGBUF8
  CLASS BLOCK ;
  FOREIGN REGBUF8 10.800 -0.000 ;
  ORIGIN 0.000 0.000 ;
  SIZE 313.200 BY 59.400 ;
  SYMMETRY X Y ;
  # ★ ピン未定義: GDS のトップにラベル/(49,1) 形状を入れて再生成すること
  OBS
    LAYER METAL1 ;
      RECT 0.000 0.000 313.200 59.400 ;
    LAYER METAL2 ;
      RECT 0.000 0.000 313.200 59.400 ;
  END
END REGBUF8

MACRO RSLATCH
  CLASS CORE ;
  FOREIGN RSLATCH -0.000 -0.000 ;
  ORIGIN 0.000 0.000 ;
  SIZE 27.000 BY 59.400 ;
  SITE TR1UM ;
  SYMMETRY X Y ;
  PIN Q
    DIRECTION INOUT ;
    USE SIGNAL ;
    PORT
      LAYER METAL2 ;
        RECT 1.000 28.000 4.400 31.400 ;
    END
  END Q
  PIN QB
    DIRECTION INOUT ;
    USE SIGNAL ;
    PORT
      LAYER METAL2 ;
        RECT 22.600 28.000 26.000 31.400 ;
    END
  END QB
  PIN R
    DIRECTION INOUT ;
    USE SIGNAL ;
    PORT
      LAYER METAL2 ;
        RECT 6.400 28.000 9.800 31.400 ;
    END
  END R
  PIN S
    DIRECTION INOUT ;
    USE SIGNAL ;
    PORT
      LAYER METAL2 ;
        RECT 17.200 28.000 20.600 31.400 ;
    END
  END S
  PIN vdd
    DIRECTION INOUT ;
    USE POWER ;
    SHAPE ABUTMENT ;
    PORT
      LAYER METAL1 ;
        POLYGON 15.500 40.700 15.500 55.700 27.000 55.700 27.000 58.300 0.000 58.300 0.000 55.700 12.900 55.700 12.900 40.700 ;
    END
  END vdd
  PIN vss
    DIRECTION INOUT ;
    USE GROUND ;
    SHAPE ABUTMENT ;
    PORT
      LAYER METAL1 ;
        POLYGON 0.000 1.100 27.000 1.100 27.000 3.700 23.500 3.700 23.500 19.600 20.900 19.600 20.900 3.700 15.500 3.700 15.500 19.600 12.900 19.600 12.900 3.700 7.500 3.700 7.500 19.600 4.900 19.600 4.900 3.700 0.000 3.700 ;
    END
  END vss
  OBS
    LAYER METAL1 ;
      POLYGON 26.000 39.700 21.700 39.700 21.700 48.300 26.000 48.300 26.000 50.900 19.100 50.900 19.100 37.900 24.200 37.900 24.200 31.400 26.000 31.400 ;
      POLYGON 2.800 37.900 9.300 37.900 9.300 50.900 6.700 50.900 6.700 39.700 1.000 39.700 1.000 31.400 2.800 31.400 ;
      POLYGON 20.600 36.500 14.100 36.500 14.100 33.900 17.200 33.900 17.200 31.400 20.600 31.400 ;
      POLYGON 9.800 28.000 12.700 28.000 12.700 36.500 10.100 36.500 10.100 31.400 9.800 31.400 ;
      POLYGON 16.900 22.900 16.900 16.200 19.500 16.200 19.500 21.100 26.000 21.100 26.000 28.000 24.200 28.000 24.200 22.900 ;
      POLYGON 8.900 21.100 8.900 11.000 11.500 11.000 11.500 22.900 2.800 22.900 2.800 28.000 1.000 28.000 1.000 21.100 ;
  END
END RSLATCH

MACRO TAP2
  CLASS CORE WELLTAP ;
  FOREIGN TAP2 -0.000 -0.000 ;
  ORIGIN 0.000 0.000 ;
  SIZE 10.800 BY 59.400 ;
  SITE TR1UM ;
  SYMMETRY X Y ;
  PIN vdd
    DIRECTION INOUT ;
    USE POWER ;
    SHAPE ABUTMENT ;
    PORT
      LAYER METAL2 ;
        RECT 6.400 54.900 9.800 58.300 ;
        RECT 6.400 1.100 9.800 4.500 ;
      LAYER METAL1 ;
        POLYGON 9.800 55.700 10.800 55.700 10.800 58.300 0.000 58.300 0.000 55.700 6.400 55.700 6.400 53.100 9.800 53.100 ;
    END
  END vdd
  PIN vss
    DIRECTION INOUT ;
    USE GROUND ;
    SHAPE ABUTMENT ;
    PORT
      LAYER METAL2 ;
        RECT 1.000 54.900 4.400 58.300 ;
        RECT 1.000 1.100 4.400 4.500 ;
      LAYER METAL1 ;
        POLYGON 10.800 3.700 4.400 3.700 4.400 6.300 1.000 6.300 1.000 3.700 0.000 3.700 0.000 1.100 10.800 1.100 ;
    END
  END vss
  OBS
    LAYER METAL2 ;
      RECT 6.400 4.500 9.800 53.100 ;
      RECT 1.000 6.300 4.400 54.900 ;
  END
END TAP2

MACRO TAP2S
  CLASS BLOCK ;
  FOREIGN TAP2S -0.000 -0.000 ;
  ORIGIN 0.000 0.000 ;
  SIZE 10.800 BY 59.400 ;
  SYMMETRY X Y ;
  PIN vdd
    DIRECTION INOUT ;
    USE POWER ;
    SHAPE ABUTMENT ;
    PORT
      LAYER METAL2 ;
        RECT 6.400 54.900 9.800 58.300 ;
    END
  END vdd
  PIN vss
    DIRECTION INOUT ;
    USE GROUND ;
    SHAPE ABUTMENT ;
    PORT
      LAYER METAL2 ;
        RECT 1.000 54.900 4.400 58.300 ;
    END
  END vss
  OBS
    LAYER METAL1 ;
      RECT 0.000 55.700 1.000 58.300 ;
      RECT 4.400 55.700 6.400 58.300 ;
      RECT 9.800 55.700 10.800 58.300 ;
      RECT 6.400 53.100 9.800 54.900 ;
      POLYGON 10.800 3.700 4.400 3.700 4.400 6.300 1.000 6.300 1.000 3.700 0.000 3.700 0.000 1.100 10.800 1.100 ;
    LAYER METAL2 ;
      RECT 1.000 1.100 4.400 54.900 ;
      RECT 6.400 1.100 9.800 54.900 ;
  END
END TAP2S

MACRO TAP3
  CLASS CORE WELLTAP ;
  FOREIGN TAP3 -0.000 -0.000 ;
  ORIGIN 0.000 0.000 ;
  SIZE 16.200 BY 59.400 ;
  SITE TR1UM ;
  SYMMETRY X Y ;
  PIN vdd
    DIRECTION INOUT ;
    USE POWER ;
    SHAPE ABUTMENT ;
    PORT
      LAYER METAL2 ;
        RECT 11.800 54.900 15.200 58.300 ;
        RECT 11.800 1.100 15.200 4.500 ;
      LAYER METAL1 ;
        POLYGON 15.200 55.700 16.200 55.700 16.200 58.300 0.000 58.300 0.000 55.700 11.800 55.700 11.800 53.100 15.200 53.100 ;
    END
  END vdd
  PIN vss
    DIRECTION INOUT ;
    USE GROUND ;
    SHAPE ABUTMENT ;
    PORT
      LAYER METAL2 ;
        RECT 1.000 54.900 4.400 58.300 ;
        RECT 1.000 1.100 4.400 4.500 ;
      LAYER METAL1 ;
        POLYGON 16.200 3.700 4.400 3.700 4.400 6.300 1.000 6.300 1.000 3.700 0.000 3.700 0.000 1.100 16.200 1.100 ;
    END
  END vss
  OBS
    LAYER METAL2 ;
      RECT 11.800 4.500 15.200 53.100 ;
      RECT 1.000 6.300 4.400 54.900 ;
  END
END TAP3

MACRO TLAT
  CLASS BLOCK ;
  FOREIGN TLAT -0.000 -0.000 ;
  ORIGIN 0.000 0.000 ;
  SIZE 37.800 BY 59.400 ;
  SYMMETRY X Y ;
  PIN D
    DIRECTION INOUT ;
    USE SIGNAL ;
    PORT
      LAYER METAL2 ;
        RECT 1.000 28.100 4.400 31.500 ;
    END
  END D
  PIN Q
    DIRECTION INOUT ;
    USE SIGNAL ;
    PORT
      LAYER METAL2 ;
        RECT 33.400 28.100 36.800 31.500 ;
    END
  END Q
  PIN RD
    DIRECTION INOUT ;
    USE SIGNAL ;
    PORT
      LAYER METAL1 ;
        POLYGON 28.600 5.500 36.800 5.500 36.800 7.300 28.600 7.300 28.600 7.700 26.000 7.700 26.000 5.100 28.600 5.100 ;
        POLYGON 16.800 7.700 14.200 7.700 14.200 7.300 -1.000 7.300 -1.000 5.500 14.200 5.500 14.200 5.100 16.800 5.100 ;
    END
  END RD
  PIN RDB
    DIRECTION INOUT ;
    USE SIGNAL ;
    PORT
      LAYER METAL1 ;
        POLYGON 28.800 52.100 36.800 52.100 36.800 53.900 28.800 53.900 28.800 54.300 26.200 54.300 26.200 51.700 28.800 51.700 ;
        POLYGON 16.800 54.300 14.200 54.300 14.200 53.900 -1.000 53.900 -1.000 52.100 14.200 52.100 14.200 51.700 16.800 51.700 ;
    END
  END RDB
  PIN WR
    DIRECTION INOUT ;
    USE SIGNAL ;
    PORT
      LAYER METAL1 ;
        POLYGON 24.800 48.500 36.800 48.500 36.800 50.300 24.800 50.300 24.800 51.000 22.200 51.000 22.200 48.400 24.800 48.400 ;
        POLYGON 13.000 50.700 10.400 50.700 10.400 50.300 -1.000 50.300 -1.000 48.500 10.400 48.500 10.400 48.100 13.000 48.100 ;
    END
  END WR
  PIN WRB
    DIRECTION INOUT ;
    USE SIGNAL ;
    PORT
      LAYER METAL1 ;
        POLYGON 24.800 9.100 36.800 9.100 36.800 10.900 24.800 10.900 24.800 11.300 22.200 11.300 22.200 8.700 24.800 8.700 ;
        POLYGON 13.000 11.300 10.400 11.300 10.400 10.900 -1.000 10.900 -1.000 9.100 10.400 9.100 10.400 8.700 13.000 8.700 ;
    END
  END WRB
  PIN vdd
    DIRECTION INOUT ;
    USE POWER ;
    SHAPE ABUTMENT ;
    PORT
      LAYER METAL1 ;
        POLYGON 20.800 36.900 20.800 44.900 26.200 44.900 26.200 36.900 28.800 36.900 28.800 46.700 20.800 46.700 20.800 55.700 37.800 55.700 37.800 58.300 0.000 58.300 0.000 55.700 18.200 55.700 18.200 36.900 ;
    END
  END vdd
  PIN vss
    DIRECTION INOUT ;
    USE GROUND ;
    SHAPE ABUTMENT ;
    PORT
      LAYER METAL1 ;
        POLYGON 0.000 1.100 37.800 1.100 37.800 3.700 20.800 3.700 20.800 13.200 28.800 13.200 28.800 19.200 26.200 19.200 26.200 15.000 20.800 15.000 20.800 19.200 18.200 19.200 18.200 3.700 0.000 3.700 ;
    END
  END vss
  OBS
    LAYER METAL1 ;
      POLYGON 32.800 19.200 32.000 19.200 32.000 36.900 32.800 36.900 32.800 43.500 30.200 43.500 30.200 16.600 32.800 16.600 ;
      POLYGON 12.800 29.000 13.800 29.000 13.800 31.600 12.800 31.600 12.800 43.500 10.200 43.500 10.200 36.900 11.000 36.900 11.000 19.200 10.200 19.200 10.200 16.600 12.800 16.600 ;
      POLYGON 16.800 20.600 18.000 20.600 18.000 35.500 16.800 35.500 16.800 43.500 14.200 43.500 14.200 33.700 16.200 33.700 16.200 22.400 14.200 22.400 14.200 16.600 16.800 16.600 ;
      POLYGON 36.800 43.500 34.200 43.500 34.200 36.900 35.000 36.900 35.000 31.500 36.800 31.500 ;
      POLYGON 24.800 29.000 25.800 29.000 25.800 31.600 24.800 31.600 24.800 43.500 22.200 43.500 22.200 36.900 23.000 36.900 23.000 19.300 22.200 19.300 22.200 16.600 24.800 16.600 ;
      POLYGON 6.200 28.100 6.200 16.600 8.800 16.600 8.800 43.500 6.200 43.500 6.200 31.500 4.400 31.500 4.400 28.100 ;
      POLYGON 36.800 28.100 35.000 28.100 35.000 19.200 34.200 19.200 34.200 16.600 36.800 16.600 ;
  END
END TLAT

MACRO TLAT128
  CLASS BLOCK ;
  FOREIGN TLAT128 -0.000 -0.000 ;
  ORIGIN 0.000 0.000 ;
  SIZE 313.200 BY 878.400 ;
  SYMMETRY X Y ;
  # ★ ピン未定義: GDS のトップにラベル/(49,1) 形状を入れて再生成すること
  OBS
    LAYER METAL1 ;
      RECT 0.000 0.000 313.200 878.400 ;
    LAYER METAL2 ;
      RECT 0.000 0.000 313.200 878.400 ;
  END
END TLAT128

MACRO TLAT4
  CLASS BLOCK ;
  FOREIGN TLAT4 -0.000 -0.000 ;
  ORIGIN 0.000 0.000 ;
  SIZE 162.000 BY 59.400 ;
  SYMMETRY X Y ;
  # ★ ピン未定義: GDS のトップにラベル/(49,1) 形状を入れて再生成すること
  OBS
    LAYER METAL1 ;
      RECT 0.000 0.000 162.000 59.400 ;
    LAYER METAL2 ;
      RECT 0.000 0.000 162.000 59.400 ;
  END
END TLAT4

MACRO TLAT4B
  CLASS BLOCK ;
  FOREIGN TLAT4B -0.000 -0.000 ;
  ORIGIN 0.000 0.000 ;
  SIZE 162.000 BY 114.000 ;
  SYMMETRY X Y ;
  # ★ ピン未定義: GDS のトップにラベル/(49,1) 形状を入れて再生成すること
  OBS
    LAYER METAL1 ;
      RECT 0.000 0.000 162.000 114.000 ;
    LAYER METAL2 ;
      RECT 0.000 0.000 162.000 114.000 ;
  END
END TLAT4B

MACRO TLAT64
  CLASS BLOCK ;
  FOREIGN TLAT64 -0.000 -0.000 ;
  ORIGIN 0.000 0.000 ;
  SIZE 162.000 BY 878.400 ;
  SYMMETRY X Y ;
  # ★ ピン未定義: GDS のトップにラベル/(49,1) 形状を入れて再生成すること
  OBS
    LAYER METAL1 ;
      RECT 0.000 0.000 162.000 878.400 ;
    LAYER METAL2 ;
      RECT 0.000 0.000 162.000 878.400 ;
  END
END TLAT64

MACRO TLAT8
  CLASS BLOCK ;
  FOREIGN TLAT8 -0.000 -0.000 ;
  ORIGIN 0.000 0.000 ;
  SIZE 313.200 BY 59.400 ;
  SYMMETRY X Y ;
  # ★ ピン未定義: GDS のトップにラベル/(49,1) 形状を入れて再生成すること
  OBS
    LAYER METAL1 ;
      RECT 0.000 0.000 313.200 59.400 ;
    LAYER METAL2 ;
      RECT 0.000 0.000 313.200 59.400 ;
  END
END TLAT8

MACRO TLAT8B
  CLASS BLOCK ;
  FOREIGN TLAT8B -0.000 -0.000 ;
  ORIGIN 0.000 0.000 ;
  SIZE 313.200 BY 114.000 ;
  SYMMETRY X Y ;
  # ★ ピン未定義: GDS のトップにラベル/(49,1) 形状を入れて再生成すること
  OBS
    LAYER METAL1 ;
      RECT 0.000 0.000 313.200 114.000 ;
    LAYER METAL2 ;
      RECT 0.000 0.000 313.200 114.000 ;
  END
END TLAT8B

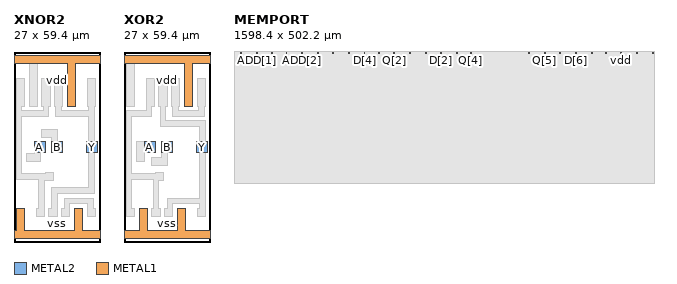
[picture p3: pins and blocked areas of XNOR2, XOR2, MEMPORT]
MACRO XNOR2
  CLASS CORE ;
  FOREIGN XNOR2 -0.000 -0.000 ;
  ORIGIN 0.000 0.000 ;
  SIZE 27.000 BY 59.400 ;
  SITE TR1UM ;
  SYMMETRY X Y ;
  PIN A
    DIRECTION INOUT ;
    USE SIGNAL ;
    PORT
      LAYER METAL2 ;
        RECT 6.400 27.900 9.800 31.300 ;
    END
  END A
  PIN B
    DIRECTION INOUT ;
    USE SIGNAL ;
    PORT
      LAYER METAL2 ;
        RECT 11.800 27.900 15.200 31.300 ;
    END
  END B
  PIN Y
    DIRECTION INOUT ;
    USE SIGNAL ;
    PORT
      LAYER METAL2 ;
        RECT 22.600 27.900 26.000 31.300 ;
    END
  END Y
  PIN vdd
    DIRECTION INOUT ;
    USE POWER ;
    SHAPE ABUTMENT ;
    PORT
      LAYER METAL1 ;
        POLYGON 19.300 42.500 19.300 55.700 27.000 55.700 27.000 58.300 0.000 58.300 0.000 55.700 16.700 55.700 16.700 42.500 ;
    END
  END vdd
  PIN vss
    DIRECTION INOUT ;
    USE GROUND ;
    SHAPE ABUTMENT ;
    PORT
      LAYER METAL1 ;
        POLYGON 0.000 1.100 27.000 1.100 27.000 3.700 21.500 3.700 21.500 10.500 18.900 10.500 18.900 3.700 3.300 3.700 3.300 10.500 0.700 10.500 0.700 3.700 0.000 3.700 ;
    END
  END vss
  OBS
    LAYER METAL1 ;
      RECT 4.700 42.500 7.300 55.700 ;
      POLYGON 25.100 42.500 25.500 42.500 25.500 51.100 22.900 51.100 22.900 42.500 23.300 42.500 23.300 41.100 14.900 41.100 14.900 42.500 15.300 42.500 15.300 51.100 12.700 51.100 12.700 42.500 13.100 42.500 13.100 39.300 23.300 39.300 23.300 31.300 25.100 31.300 ;
      POLYGON 9.500 19.100 12.300 19.100 12.300 21.700 9.700 21.700 9.700 21.400 2.500 21.400 2.500 39.300 10.900 39.300 10.900 42.500 11.300 42.500 11.300 51.100 8.700 51.100 8.700 42.500 9.100 42.500 9.100 41.100 2.500 41.100 2.500 42.500 3.300 42.500 3.300 51.100 0.700 51.100 0.700 19.600 7.700 19.600 7.700 10.500 6.900 10.500 6.900 7.900 9.500 7.900 ;
      POLYGON 13.600 35.300 8.700 35.300 8.700 32.700 11.800 32.700 11.800 31.300 13.600 31.300 ;
      POLYGON 3.900 27.700 3.900 25.100 8.200 25.100 8.200 27.900 6.400 27.900 6.400 27.700 ;
      POLYGON 17.500 11.900 22.900 11.900 22.900 7.900 25.500 7.900 25.500 10.500 24.700 10.500 24.700 13.700 15.700 13.700 15.700 10.500 14.900 10.500 14.900 7.900 17.500 7.900 ;
      POLYGON 11.700 16.900 11.700 10.500 10.900 10.500 10.900 7.900 13.500 7.900 13.500 15.100 25.100 15.100 25.100 27.900 23.300 27.900 23.300 16.900 ;
  END
END XNOR2

MACRO XOR2
  CLASS CORE ;
  FOREIGN XOR2 -0.000 -0.000 ;
  ORIGIN 0.000 0.000 ;
  SIZE 27.000 BY 59.400 ;
  SITE TR1UM ;
  SYMMETRY X Y ;
  PIN A
    DIRECTION INOUT ;
    USE SIGNAL ;
    PORT
      LAYER METAL2 ;
        RECT 6.400 27.900 9.800 31.300 ;
    END
  END A
  PIN B
    DIRECTION INOUT ;
    USE SIGNAL ;
    PORT
      LAYER METAL2 ;
        RECT 11.800 27.900 15.200 31.300 ;
    END
  END B
  PIN Y
    DIRECTION INOUT ;
    USE SIGNAL ;
    PORT
      LAYER METAL2 ;
        RECT 22.600 27.900 26.000 31.300 ;
    END
  END Y
  PIN vdd
    DIRECTION INOUT ;
    USE POWER ;
    SHAPE ABUTMENT ;
    PORT
      LAYER METAL1 ;
        POLYGON 21.500 42.500 21.500 55.700 27.000 55.700 27.000 58.300 0.000 58.300 0.000 55.700 18.900 55.700 18.900 42.500 ;
    END
  END vdd
  PIN vss
    DIRECTION INOUT ;
    USE GROUND ;
    SHAPE ABUTMENT ;
    PORT
      LAYER METAL1 ;
        POLYGON 0.000 1.100 27.000 1.100 27.000 3.700 19.300 3.700 19.300 10.500 16.700 10.500 16.700 3.700 7.300 3.700 7.300 10.500 4.700 10.500 4.700 3.700 0.000 3.700 ;
    END
  END vss
  OBS
    LAYER METAL1 ;
      RECT 0.700 42.500 3.300 55.700 ;
      POLYGON 25.100 42.500 25.500 42.500 25.500 51.100 22.900 51.100 22.900 42.500 23.300 42.500 23.300 41.100 17.100 41.100 17.100 42.500 17.500 42.500 17.500 51.100 14.900 51.100 14.900 42.500 15.300 42.500 15.300 39.300 25.100 39.300 ;
      POLYGON 25.400 37.900 13.100 37.900 13.100 42.500 13.500 42.500 13.500 51.100 10.900 51.100 10.900 42.500 11.300 42.500 11.300 36.100 23.600 36.100 23.600 31.300 25.400 31.300 ;
      POLYGON 3.300 10.500 2.500 10.500 2.500 19.600 9.100 19.600 9.100 10.500 8.700 10.500 8.700 7.900 11.300 7.900 11.300 10.500 10.900 10.500 10.900 19.100 12.300 19.100 12.300 21.700 9.700 21.700 9.700 21.400 2.500 21.400 2.500 39.300 8.700 39.300 8.700 42.500 9.500 42.500 9.500 51.100 6.900 51.100 6.900 41.100 0.700 41.100 0.700 7.900 3.300 7.900 ;
      POLYGON 6.500 27.900 6.400 27.900 6.400 31.300 3.900 31.300 3.900 25.100 6.500 25.100 ;
      POLYGON 13.600 27.900 11.800 27.900 11.800 26.500 8.700 26.500 8.700 23.900 13.600 23.900 ;
      POLYGON 13.500 13.700 13.500 10.500 12.700 10.500 12.700 7.900 15.300 7.900 15.300 11.900 23.600 11.900 23.600 10.500 22.900 10.500 22.900 7.900 25.500 7.900 25.500 10.500 25.400 10.500 25.400 27.900 23.600 27.900 23.600 13.700 ;
  END
END XOR2

END LIBRARY
MACRO MEMPORT
  CLASS BLOCK ;
  FOREIGN MEMPORT 0.000 0.000 ;
  ORIGIN 0.000 0.000 ;
  SIZE 1598.400 BY 502.200 ;
  SYMMETRY X Y ;
  PIN Q[3]
    DIRECTION INOUT ;
    USE SIGNAL ;
    PORT
      LAYER METAL2 ;
        RECT 25.300 493.100 28.700 496.500 ;
    END
  END Q[3]
  PIN ADD[1]
    DIRECTION INOUT ;
    USE SIGNAL ;
    PORT
      LAYER METAL2 ;
        RECT 84.700 493.100 88.100 496.500 ;
    END
  END ADD[1]
  PIN ADD[0]
    DIRECTION INOUT ;
    USE SIGNAL ;
    PORT
      LAYER METAL2 ;
        RECT 144.100 493.100 147.500 496.500 ;
    END
  END ADD[0]
  PIN ADD[3]
    DIRECTION INOUT ;
    USE SIGNAL ;
    PORT
      LAYER METAL2 ;
        RECT 198.100 493.100 201.500 496.500 ;
    END
  END ADD[3]
  PIN ADD[2]
    DIRECTION INOUT ;
    USE SIGNAL ;
    PORT
      LAYER METAL2 ;
        RECT 257.500 493.100 260.900 496.500 ;
    END
  END ADD[2]
  PIN WEB
    DIRECTION INOUT ;
    USE SIGNAL ;
    PORT
      LAYER METAL2 ;
        RECT 316.900 493.100 320.300 496.500 ;
    END
  END WEB
  PIN D[0]
    DIRECTION INOUT ;
    USE SIGNAL ;
    PORT
      LAYER METAL2 ;
        RECT 376.300 493.100 379.700 496.500 ;
    END
  END D[0]
  PIN D[3]
    DIRECTION INOUT ;
    USE SIGNAL ;
    PORT
      LAYER METAL2 ;
        RECT 435.700 493.100 439.100 496.500 ;
    END
  END D[3]
  PIN D[4]
    DIRECTION INOUT ;
    USE SIGNAL ;
    PORT
      LAYER METAL2 ;
        RECT 495.100 493.100 498.500 496.500 ;
    END
  END D[4]
  PIN D[7]
    DIRECTION INOUT ;
    USE SIGNAL ;
    PORT
      LAYER METAL2 ;
        RECT 549.100 493.100 552.500 496.500 ;
    END
  END D[7]
  PIN Q[2]
    DIRECTION INOUT ;
    USE SIGNAL ;
    PORT
      LAYER METAL2 ;
        RECT 608.500 493.100 611.900 496.500 ;
    END
  END Q[2]
  PIN Q[6]
    DIRECTION INOUT ;
    USE SIGNAL ;
    PORT
      LAYER METAL2 ;
        RECT 667.900 493.100 671.300 496.500 ;
    END
  END Q[6]
  PIN D[1]
    DIRECTION INOUT ;
    USE SIGNAL ;
    PORT
      LAYER METAL2 ;
        RECT 727.300 493.100 730.700 496.500 ;
    END
  END D[1]
  PIN D[2]
    DIRECTION INOUT ;
    USE SIGNAL ;
    PORT
      LAYER METAL2 ;
        RECT 786.700 493.100 790.100 496.500 ;
    END
  END D[2]
  PIN Q[0]
    DIRECTION INOUT ;
    USE SIGNAL ;
    PORT
      LAYER METAL2 ;
        RECT 846.100 493.100 849.500 496.500 ;
    END
  END Q[0]
  PIN Q[4]
    DIRECTION INOUT ;
    USE SIGNAL ;
    PORT
      LAYER METAL2 ;
        RECT 900.100 493.100 903.500 496.500 ;
    END
  END Q[4]
  PIN Q[7]
    DIRECTION INOUT ;
    USE SIGNAL ;
    PORT
      LAYER METAL2 ;
        RECT 1121.500 493.100 1124.900 496.500 ;
    END
  END Q[7]
  PIN Q[5]
    DIRECTION INOUT ;
    USE SIGNAL ;
    PORT
      LAYER METAL2 ;
        RECT 1180.900 493.100 1184.300 496.500 ;
    END
  END Q[5]
  PIN Q[1]
    DIRECTION INOUT ;
    USE SIGNAL ;
    PORT
      LAYER METAL2 ;
        RECT 1240.300 493.100 1243.700 496.500 ;
    END
  END Q[1]
  PIN D[6]
    DIRECTION INOUT ;
    USE SIGNAL ;
    PORT
      LAYER METAL2 ;
        RECT 1299.700 493.100 1303.100 496.500 ;
    END
  END D[6]
  PIN D[5]
    DIRECTION INOUT ;
    USE SIGNAL ;
    PORT
      LAYER METAL2 ;
        RECT 1359.100 493.100 1362.500 496.500 ;
    END
  END D[5]
  PIN vss
    DIRECTION INOUT ;
    USE GROUND ;
    PORT
      LAYER METAL2 ;
        RECT 1413.100 493.100 1416.500 496.500 ;
        RECT 1531.900 493.100 1535.300 496.500 ;
    END
  END vss
  PIN vdd
    DIRECTION INOUT ;
    USE POWER ;
    PORT
      LAYER METAL2 ;
        RECT 1472.500 493.100 1475.900 496.500 ;
        RECT 1591.300 493.100 1594.700 496.500 ;
    END
  END vdd
  OBS
    LAYER METAL1 ;
      RECT 0.000 0.000 1598.400 502.200 ;
    LAYER METAL2 ;
      RECT 0.000 0.000 1598.400 502.200 ;
  END
END MEMPORT
